VERSION 5.8 ;
BUSBITCHARS "[]" ;
DIVIDERCHAR "/" ;
UNITS
    DATABASE MICRONS 1000 ;
END UNITS

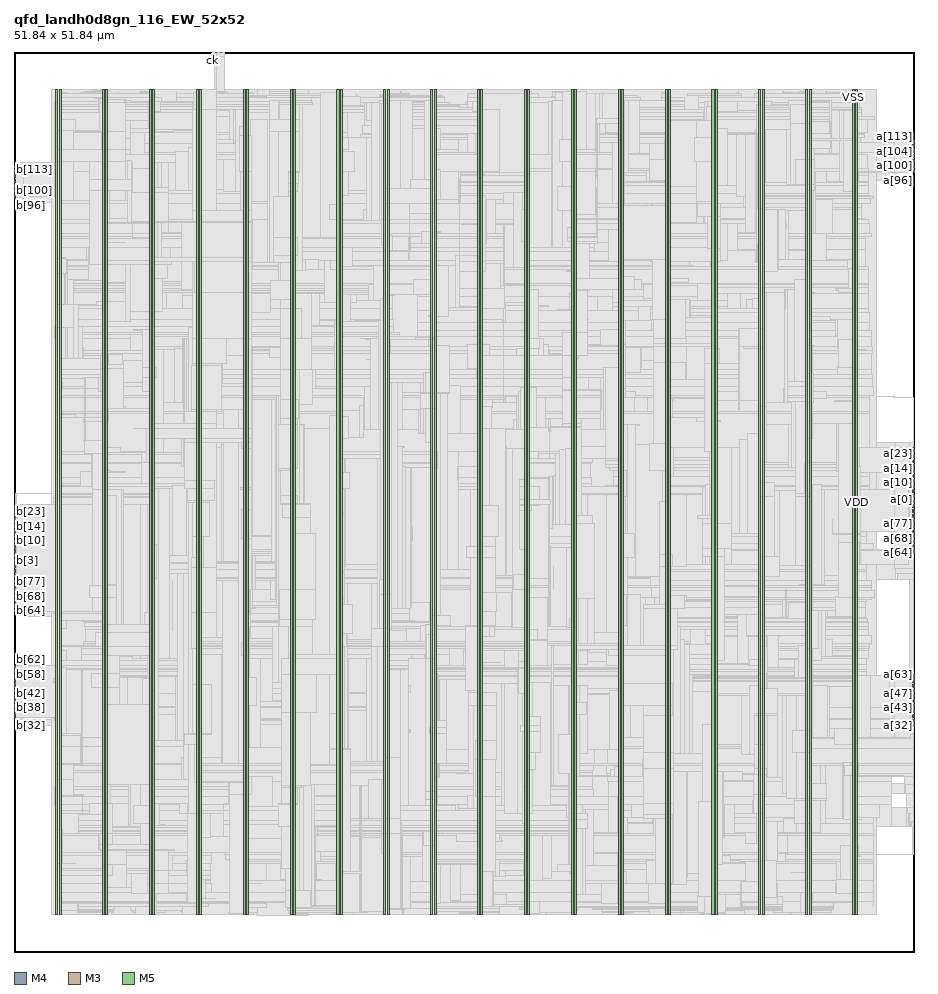
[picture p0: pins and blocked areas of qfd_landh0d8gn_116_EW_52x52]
MACRO qfd_landh0d8gn_116_EW_52x52
  FOREIGN qfd_landh0d8gn_116_EW_52x52 0 0 ;
  CLASS BLOCK ;
  SIZE 51.84 BY 51.84 ;
  PIN a[0]
    DIRECTION INPUT ;
    USE SIGNAL ;
    PORT
      LAYER M4 ;
        RECT  51.756 26.064 51.84 26.088 ;
    END
  END a[0]
  PIN a[100]
    DIRECTION INPUT ;
    USE SIGNAL ;
    PORT
      LAYER M4 ;
        RECT  51.756 45.264 51.84 45.288 ;
    END
  END a[100]
  PIN a[101]
    DIRECTION INPUT ;
    USE SIGNAL ;
    PORT
      LAYER M4 ;
        RECT  51.756 45.36 51.84 45.384 ;
    END
  END a[101]
  PIN a[102]
    DIRECTION INPUT ;
    USE SIGNAL ;
    PORT
      LAYER M4 ;
        RECT  51.756 45.456 51.84 45.48 ;
    END
  END a[102]
  PIN a[103]
    DIRECTION INPUT ;
    USE SIGNAL ;
    PORT
      LAYER M4 ;
        RECT  51.756 45.552 51.84 45.576 ;
    END
  END a[103]
  PIN a[104]
    DIRECTION INPUT ;
    USE SIGNAL ;
    PORT
      LAYER M4 ;
        RECT  51.756 45.648 51.84 45.672 ;
    END
  END a[104]
  PIN a[105]
    DIRECTION INPUT ;
    USE SIGNAL ;
    PORT
      LAYER M4 ;
        RECT  51.756 45.744 51.84 45.768 ;
    END
  END a[105]
  PIN a[106]
    DIRECTION INPUT ;
    USE SIGNAL ;
    PORT
      LAYER M4 ;
        RECT  51.756 45.84 51.84 45.864 ;
    END
  END a[106]
  PIN a[107]
    DIRECTION INPUT ;
    USE SIGNAL ;
    PORT
      LAYER M4 ;
        RECT  51.756 45.936 51.84 45.96 ;
    END
  END a[107]
  PIN a[108]
    DIRECTION INPUT ;
    USE SIGNAL ;
    PORT
      LAYER M4 ;
        RECT  51.756 46.032 51.84 46.056 ;
    END
  END a[108]
  PIN a[109]
    DIRECTION INPUT ;
    USE SIGNAL ;
    PORT
      LAYER M4 ;
        RECT  51.756 46.128 51.84 46.152 ;
    END
  END a[109]
  PIN a[10]
    DIRECTION INPUT ;
    USE SIGNAL ;
    PORT
      LAYER M4 ;
        RECT  51.756 27.024 51.84 27.048 ;
    END
  END a[10]
  PIN a[110]
    DIRECTION INPUT ;
    USE SIGNAL ;
    PORT
      LAYER M4 ;
        RECT  51.756 46.224 51.84 46.248 ;
    END
  END a[110]
  PIN a[111]
    DIRECTION INPUT ;
    USE SIGNAL ;
    PORT
      LAYER M4 ;
        RECT  51.756 46.32 51.84 46.344 ;
    END
  END a[111]
  PIN a[112]
    DIRECTION INPUT ;
    USE SIGNAL ;
    PORT
      LAYER M4 ;
        RECT  51.756 46.416 51.84 46.44 ;
    END
  END a[112]
  PIN a[113]
    DIRECTION INPUT ;
    USE SIGNAL ;
    PORT
      LAYER M4 ;
        RECT  51.756 46.512 51.84 46.536 ;
    END
  END a[113]
  PIN a[114]
    DIRECTION INPUT ;
    USE SIGNAL ;
    PORT
      LAYER M4 ;
        RECT  51.756 46.608 51.84 46.632 ;
    END
  END a[114]
  PIN a[115]
    DIRECTION INPUT ;
    USE SIGNAL ;
    PORT
      LAYER M4 ;
        RECT  51.756 46.704 51.84 46.728 ;
    END
  END a[115]
  PIN a[11]
    DIRECTION INPUT ;
    USE SIGNAL ;
    PORT
      LAYER M4 ;
        RECT  51.756 27.12 51.84 27.144 ;
    END
  END a[11]
  PIN a[12]
    DIRECTION INPUT ;
    USE SIGNAL ;
    PORT
      LAYER M4 ;
        RECT  51.756 27.216 51.84 27.24 ;
    END
  END a[12]
  PIN a[13]
    DIRECTION INPUT ;
    USE SIGNAL ;
    PORT
      LAYER M4 ;
        RECT  51.756 27.312 51.84 27.336 ;
    END
  END a[13]
  PIN a[14]
    DIRECTION INPUT ;
    USE SIGNAL ;
    PORT
      LAYER M4 ;
        RECT  51.756 27.408 51.84 27.432 ;
    END
  END a[14]
  PIN a[15]
    DIRECTION INPUT ;
    USE SIGNAL ;
    PORT
      LAYER M4 ;
        RECT  51.756 27.504 51.84 27.528 ;
    END
  END a[15]
  PIN a[16]
    DIRECTION INPUT ;
    USE SIGNAL ;
    PORT
      LAYER M4 ;
        RECT  51.756 27.6 51.84 27.624 ;
    END
  END a[16]
  PIN a[17]
    DIRECTION INPUT ;
    USE SIGNAL ;
    PORT
      LAYER M4 ;
        RECT  51.756 27.696 51.84 27.72 ;
    END
  END a[17]
  PIN a[18]
    DIRECTION INPUT ;
    USE SIGNAL ;
    PORT
      LAYER M4 ;
        RECT  51.756 27.792 51.84 27.816 ;
    END
  END a[18]
  PIN a[19]
    DIRECTION INPUT ;
    USE SIGNAL ;
    PORT
      LAYER M4 ;
        RECT  51.756 27.888 51.84 27.912 ;
    END
  END a[19]
  PIN a[1]
    DIRECTION INPUT ;
    USE SIGNAL ;
    PORT
      LAYER M4 ;
        RECT  51.756 26.16 51.84 26.184 ;
    END
  END a[1]
  PIN a[20]
    DIRECTION INPUT ;
    USE SIGNAL ;
    PORT
      LAYER M4 ;
        RECT  51.756 27.984 51.84 28.008 ;
    END
  END a[20]
  PIN a[21]
    DIRECTION INPUT ;
    USE SIGNAL ;
    PORT
      LAYER M4 ;
        RECT  51.756 28.08 51.84 28.104 ;
    END
  END a[21]
  PIN a[22]
    DIRECTION INPUT ;
    USE SIGNAL ;
    PORT
      LAYER M4 ;
        RECT  51.756 28.176 51.84 28.2 ;
    END
  END a[22]
  PIN a[23]
    DIRECTION INPUT ;
    USE SIGNAL ;
    PORT
      LAYER M4 ;
        RECT  51.756 28.272 51.84 28.296 ;
    END
  END a[23]
  PIN a[24]
    DIRECTION INPUT ;
    USE SIGNAL ;
    PORT
      LAYER M4 ;
        RECT  51.756 28.368 51.84 28.392 ;
    END
  END a[24]
  PIN a[25]
    DIRECTION INPUT ;
    USE SIGNAL ;
    PORT
      LAYER M4 ;
        RECT  51.756 28.464 51.84 28.488 ;
    END
  END a[25]
  PIN a[26]
    DIRECTION INPUT ;
    USE SIGNAL ;
    PORT
      LAYER M4 ;
        RECT  51.756 28.56 51.84 28.584 ;
    END
  END a[26]
  PIN a[27]
    DIRECTION INPUT ;
    USE SIGNAL ;
    PORT
      LAYER M4 ;
        RECT  51.756 28.656 51.84 28.68 ;
    END
  END a[27]
  PIN a[28]
    DIRECTION INPUT ;
    USE SIGNAL ;
    PORT
      LAYER M4 ;
        RECT  51.756 28.752 51.84 28.776 ;
    END
  END a[28]
  PIN a[29]
    DIRECTION INPUT ;
    USE SIGNAL ;
    PORT
      LAYER M4 ;
        RECT  51.756 28.848 51.84 28.872 ;
    END
  END a[29]
  PIN a[2]
    DIRECTION INPUT ;
    USE SIGNAL ;
    PORT
      LAYER M4 ;
        RECT  51.756 26.256 51.84 26.28 ;
    END
  END a[2]
  PIN a[30]
    DIRECTION INPUT ;
    USE SIGNAL ;
    PORT
      LAYER M4 ;
        RECT  51.756 28.944 51.84 28.968 ;
    END
  END a[30]
  PIN a[31]
    DIRECTION INPUT ;
    USE SIGNAL ;
    PORT
      LAYER M4 ;
        RECT  51.756 29.04 51.84 29.064 ;
    END
  END a[31]
  PIN a[32]
    DIRECTION INPUT ;
    USE SIGNAL ;
    PORT
      LAYER M4 ;
        RECT  51.756 13.008 51.84 13.032 ;
    END
  END a[32]
  PIN a[33]
    DIRECTION INPUT ;
    USE SIGNAL ;
    PORT
      LAYER M4 ;
        RECT  51.756 13.104 51.84 13.128 ;
    END
  END a[33]
  PIN a[34]
    DIRECTION INPUT ;
    USE SIGNAL ;
    PORT
      LAYER M4 ;
        RECT  51.756 13.2 51.84 13.224 ;
    END
  END a[34]
  PIN a[35]
    DIRECTION INPUT ;
    USE SIGNAL ;
    PORT
      LAYER M4 ;
        RECT  51.756 13.296 51.84 13.32 ;
    END
  END a[35]
  PIN a[36]
    DIRECTION INPUT ;
    USE SIGNAL ;
    PORT
      LAYER M4 ;
        RECT  51.756 13.392 51.84 13.416 ;
    END
  END a[36]
  PIN a[37]
    DIRECTION INPUT ;
    USE SIGNAL ;
    PORT
      LAYER M4 ;
        RECT  51.756 13.488 51.84 13.512 ;
    END
  END a[37]
  PIN a[38]
    DIRECTION INPUT ;
    USE SIGNAL ;
    PORT
      LAYER M4 ;
        RECT  51.756 13.584 51.84 13.608 ;
    END
  END a[38]
  PIN a[39]
    DIRECTION INPUT ;
    USE SIGNAL ;
    PORT
      LAYER M4 ;
        RECT  51.756 13.68 51.84 13.704 ;
    END
  END a[39]
  PIN a[3]
    DIRECTION INPUT ;
    USE SIGNAL ;
    PORT
      LAYER M4 ;
        RECT  51.756 26.352 51.84 26.376 ;
    END
  END a[3]
  PIN a[40]
    DIRECTION INPUT ;
    USE SIGNAL ;
    PORT
      LAYER M4 ;
        RECT  51.756 13.776 51.84 13.8 ;
    END
  END a[40]
  PIN a[41]
    DIRECTION INPUT ;
    USE SIGNAL ;
    PORT
      LAYER M4 ;
        RECT  51.756 13.872 51.84 13.896 ;
    END
  END a[41]
  PIN a[42]
    DIRECTION INPUT ;
    USE SIGNAL ;
    PORT
      LAYER M4 ;
        RECT  51.756 13.968 51.84 13.992 ;
    END
  END a[42]
  PIN a[43]
    DIRECTION INPUT ;
    USE SIGNAL ;
    PORT
      LAYER M4 ;
        RECT  51.756 14.064 51.84 14.088 ;
    END
  END a[43]
  PIN a[44]
    DIRECTION INPUT ;
    USE SIGNAL ;
    PORT
      LAYER M4 ;
        RECT  51.756 14.16 51.84 14.184 ;
    END
  END a[44]
  PIN a[45]
    DIRECTION INPUT ;
    USE SIGNAL ;
    PORT
      LAYER M4 ;
        RECT  51.756 14.256 51.84 14.28 ;
    END
  END a[45]
  PIN a[46]
    DIRECTION INPUT ;
    USE SIGNAL ;
    PORT
      LAYER M4 ;
        RECT  51.756 14.352 51.84 14.376 ;
    END
  END a[46]
  PIN a[47]
    DIRECTION INPUT ;
    USE SIGNAL ;
    PORT
      LAYER M4 ;
        RECT  51.756 14.448 51.84 14.472 ;
    END
  END a[47]
  PIN a[48]
    DIRECTION INPUT ;
    USE SIGNAL ;
    PORT
      LAYER M4 ;
        RECT  51.756 14.544 51.84 14.568 ;
    END
  END a[48]
  PIN a[49]
    DIRECTION INPUT ;
    USE SIGNAL ;
    PORT
      LAYER M4 ;
        RECT  51.756 14.64 51.84 14.664 ;
    END
  END a[49]
  PIN a[4]
    DIRECTION INPUT ;
    USE SIGNAL ;
    PORT
      LAYER M4 ;
        RECT  51.756 26.448 51.84 26.472 ;
    END
  END a[4]
  PIN a[50]
    DIRECTION INPUT ;
    USE SIGNAL ;
    PORT
      LAYER M4 ;
        RECT  51.756 14.736 51.84 14.76 ;
    END
  END a[50]
  PIN a[51]
    DIRECTION INPUT ;
    USE SIGNAL ;
    PORT
      LAYER M4 ;
        RECT  51.756 14.832 51.84 14.856 ;
    END
  END a[51]
  PIN a[52]
    DIRECTION INPUT ;
    USE SIGNAL ;
    PORT
      LAYER M4 ;
        RECT  51.756 14.928 51.84 14.952 ;
    END
  END a[52]
  PIN a[53]
    DIRECTION INPUT ;
    USE SIGNAL ;
    PORT
      LAYER M4 ;
        RECT  51.756 15.024 51.84 15.048 ;
    END
  END a[53]
  PIN a[54]
    DIRECTION INPUT ;
    USE SIGNAL ;
    PORT
      LAYER M4 ;
        RECT  51.756 15.12 51.84 15.144 ;
    END
  END a[54]
  PIN a[55]
    DIRECTION INPUT ;
    USE SIGNAL ;
    PORT
      LAYER M4 ;
        RECT  51.756 15.216 51.84 15.24 ;
    END
  END a[55]
  PIN a[56]
    DIRECTION INPUT ;
    USE SIGNAL ;
    PORT
      LAYER M4 ;
        RECT  51.756 15.312 51.84 15.336 ;
    END
  END a[56]
  PIN a[57]
    DIRECTION INPUT ;
    USE SIGNAL ;
    PORT
      LAYER M4 ;
        RECT  51.756 15.408 51.84 15.432 ;
    END
  END a[57]
  PIN a[58]
    DIRECTION INPUT ;
    USE SIGNAL ;
    PORT
      LAYER M4 ;
        RECT  51.756 15.504 51.84 15.528 ;
    END
  END a[58]
  PIN a[59]
    DIRECTION INPUT ;
    USE SIGNAL ;
    PORT
      LAYER M4 ;
        RECT  51.756 15.6 51.84 15.624 ;
    END
  END a[59]
  PIN a[5]
    DIRECTION INPUT ;
    USE SIGNAL ;
    PORT
      LAYER M4 ;
        RECT  51.756 26.544 51.84 26.568 ;
    END
  END a[5]
  PIN a[60]
    DIRECTION INPUT ;
    USE SIGNAL ;
    PORT
      LAYER M4 ;
        RECT  51.756 15.696 51.84 15.72 ;
    END
  END a[60]
  PIN a[61]
    DIRECTION INPUT ;
    USE SIGNAL ;
    PORT
      LAYER M4 ;
        RECT  51.756 15.792 51.84 15.816 ;
    END
  END a[61]
  PIN a[62]
    DIRECTION INPUT ;
    USE SIGNAL ;
    PORT
      LAYER M4 ;
        RECT  51.756 15.888 51.84 15.912 ;
    END
  END a[62]
  PIN a[63]
    DIRECTION INPUT ;
    USE SIGNAL ;
    PORT
      LAYER M4 ;
        RECT  51.756 15.984 51.84 16.008 ;
    END
  END a[63]
  PIN a[64]
    DIRECTION INPUT ;
    USE SIGNAL ;
    PORT
      LAYER M4 ;
        RECT  51.756 22.992 51.84 23.016 ;
    END
  END a[64]
  PIN a[65]
    DIRECTION INPUT ;
    USE SIGNAL ;
    PORT
      LAYER M4 ;
        RECT  51.756 23.088 51.84 23.112 ;
    END
  END a[65]
  PIN a[66]
    DIRECTION INPUT ;
    USE SIGNAL ;
    PORT
      LAYER M4 ;
        RECT  51.756 23.184 51.84 23.208 ;
    END
  END a[66]
  PIN a[67]
    DIRECTION INPUT ;
    USE SIGNAL ;
    PORT
      LAYER M4 ;
        RECT  51.756 23.28 51.84 23.304 ;
    END
  END a[67]
  PIN a[68]
    DIRECTION INPUT ;
    USE SIGNAL ;
    PORT
      LAYER M4 ;
        RECT  51.756 23.376 51.84 23.4 ;
    END
  END a[68]
  PIN a[69]
    DIRECTION INPUT ;
    USE SIGNAL ;
    PORT
      LAYER M4 ;
        RECT  51.756 23.472 51.84 23.496 ;
    END
  END a[69]
  PIN a[6]
    DIRECTION INPUT ;
    USE SIGNAL ;
    PORT
      LAYER M4 ;
        RECT  51.756 26.64 51.84 26.664 ;
    END
  END a[6]
  PIN a[70]
    DIRECTION INPUT ;
    USE SIGNAL ;
    PORT
      LAYER M4 ;
        RECT  51.756 23.568 51.84 23.592 ;
    END
  END a[70]
  PIN a[71]
    DIRECTION INPUT ;
    USE SIGNAL ;
    PORT
      LAYER M4 ;
        RECT  51.756 23.664 51.84 23.688 ;
    END
  END a[71]
  PIN a[72]
    DIRECTION INPUT ;
    USE SIGNAL ;
    PORT
      LAYER M4 ;
        RECT  51.756 23.76 51.84 23.784 ;
    END
  END a[72]
  PIN a[73]
    DIRECTION INPUT ;
    USE SIGNAL ;
    PORT
      LAYER M4 ;
        RECT  51.756 23.856 51.84 23.88 ;
    END
  END a[73]
  PIN a[74]
    DIRECTION INPUT ;
    USE SIGNAL ;
    PORT
      LAYER M4 ;
        RECT  51.756 23.952 51.84 23.976 ;
    END
  END a[74]
  PIN a[75]
    DIRECTION INPUT ;
    USE SIGNAL ;
    PORT
      LAYER M4 ;
        RECT  51.756 24.048 51.84 24.072 ;
    END
  END a[75]
  PIN a[76]
    DIRECTION INPUT ;
    USE SIGNAL ;
    PORT
      LAYER M4 ;
        RECT  51.756 24.144 51.84 24.168 ;
    END
  END a[76]
  PIN a[77]
    DIRECTION INPUT ;
    USE SIGNAL ;
    PORT
      LAYER M4 ;
        RECT  51.756 24.24 51.84 24.264 ;
    END
  END a[77]
  PIN a[78]
    DIRECTION INPUT ;
    USE SIGNAL ;
    PORT
      LAYER M4 ;
        RECT  51.756 24.336 51.84 24.36 ;
    END
  END a[78]
  PIN a[79]
    DIRECTION INPUT ;
    USE SIGNAL ;
    PORT
      LAYER M4 ;
        RECT  51.756 24.432 51.84 24.456 ;
    END
  END a[79]
  PIN a[7]
    DIRECTION INPUT ;
    USE SIGNAL ;
    PORT
      LAYER M4 ;
        RECT  51.756 26.736 51.84 26.76 ;
    END
  END a[7]
  PIN a[80]
    DIRECTION INPUT ;
    USE SIGNAL ;
    PORT
      LAYER M4 ;
        RECT  51.756 24.528 51.84 24.552 ;
    END
  END a[80]
  PIN a[81]
    DIRECTION INPUT ;
    USE SIGNAL ;
    PORT
      LAYER M4 ;
        RECT  51.756 24.624 51.84 24.648 ;
    END
  END a[81]
  PIN a[82]
    DIRECTION INPUT ;
    USE SIGNAL ;
    PORT
      LAYER M4 ;
        RECT  51.756 24.72 51.84 24.744 ;
    END
  END a[82]
  PIN a[83]
    DIRECTION INPUT ;
    USE SIGNAL ;
    PORT
      LAYER M4 ;
        RECT  51.756 24.816 51.84 24.84 ;
    END
  END a[83]
  PIN a[84]
    DIRECTION INPUT ;
    USE SIGNAL ;
    PORT
      LAYER M4 ;
        RECT  51.756 24.912 51.84 24.936 ;
    END
  END a[84]
  PIN a[85]
    DIRECTION INPUT ;
    USE SIGNAL ;
    PORT
      LAYER M4 ;
        RECT  51.756 25.008 51.84 25.032 ;
    END
  END a[85]
  PIN a[86]
    DIRECTION INPUT ;
    USE SIGNAL ;
    PORT
      LAYER M4 ;
        RECT  51.756 25.104 51.84 25.128 ;
    END
  END a[86]
  PIN a[87]
    DIRECTION INPUT ;
    USE SIGNAL ;
    PORT
      LAYER M4 ;
        RECT  51.756 25.2 51.84 25.224 ;
    END
  END a[87]
  PIN a[88]
    DIRECTION INPUT ;
    USE SIGNAL ;
    PORT
      LAYER M4 ;
        RECT  51.756 25.296 51.84 25.32 ;
    END
  END a[88]
  PIN a[89]
    DIRECTION INPUT ;
    USE SIGNAL ;
    PORT
      LAYER M4 ;
        RECT  51.756 25.392 51.84 25.416 ;
    END
  END a[89]
  PIN a[8]
    DIRECTION INPUT ;
    USE SIGNAL ;
    PORT
      LAYER M4 ;
        RECT  51.756 26.832 51.84 26.856 ;
    END
  END a[8]
  PIN a[90]
    DIRECTION INPUT ;
    USE SIGNAL ;
    PORT
      LAYER M4 ;
        RECT  51.756 25.488 51.84 25.512 ;
    END
  END a[90]
  PIN a[91]
    DIRECTION INPUT ;
    USE SIGNAL ;
    PORT
      LAYER M4 ;
        RECT  51.756 25.584 51.84 25.608 ;
    END
  END a[91]
  PIN a[92]
    DIRECTION INPUT ;
    USE SIGNAL ;
    PORT
      LAYER M4 ;
        RECT  51.756 25.68 51.84 25.704 ;
    END
  END a[92]
  PIN a[93]
    DIRECTION INPUT ;
    USE SIGNAL ;
    PORT
      LAYER M4 ;
        RECT  51.756 25.776 51.84 25.8 ;
    END
  END a[93]
  PIN a[94]
    DIRECTION INPUT ;
    USE SIGNAL ;
    PORT
      LAYER M4 ;
        RECT  51.756 25.872 51.84 25.896 ;
    END
  END a[94]
  PIN a[95]
    DIRECTION INPUT ;
    USE SIGNAL ;
    PORT
      LAYER M4 ;
        RECT  51.756 25.968 51.84 25.992 ;
    END
  END a[95]
  PIN a[96]
    DIRECTION INPUT ;
    USE SIGNAL ;
    PORT
      LAYER M4 ;
        RECT  51.756 44.88 51.84 44.904 ;
    END
  END a[96]
  PIN a[97]
    DIRECTION INPUT ;
    USE SIGNAL ;
    PORT
      LAYER M4 ;
        RECT  51.756 44.976 51.84 45 ;
    END
  END a[97]
  PIN a[98]
    DIRECTION INPUT ;
    USE SIGNAL ;
    PORT
      LAYER M4 ;
        RECT  51.756 45.072 51.84 45.096 ;
    END
  END a[98]
  PIN a[99]
    DIRECTION INPUT ;
    USE SIGNAL ;
    PORT
      LAYER M4 ;
        RECT  51.756 45.168 51.84 45.192 ;
    END
  END a[99]
  PIN a[9]
    DIRECTION INPUT ;
    USE SIGNAL ;
    PORT
      LAYER M4 ;
        RECT  51.756 26.928 51.84 26.952 ;
    END
  END a[9]
  PIN b[0]
    DIRECTION OUTPUT ;
    USE SIGNAL ;
    PORT
      LAYER M4 ;
        RECT  0 22.704 0.084 22.728 ;
    END
  END b[0]
  PIN b[100]
    DIRECTION OUTPUT ;
    USE SIGNAL ;
    PORT
      LAYER M4 ;
        RECT  0 43.824 0.084 43.848 ;
    END
  END b[100]
  PIN b[101]
    DIRECTION OUTPUT ;
    USE SIGNAL ;
    PORT
      LAYER M4 ;
        RECT  0 43.92 0.084 43.944 ;
    END
  END b[101]
  PIN b[102]
    DIRECTION OUTPUT ;
    USE SIGNAL ;
    PORT
      LAYER M4 ;
        RECT  0 44.016 0.084 44.04 ;
    END
  END b[102]
  PIN b[103]
    DIRECTION OUTPUT ;
    USE SIGNAL ;
    PORT
      LAYER M4 ;
        RECT  0 44.112 0.084 44.136 ;
    END
  END b[103]
  PIN b[104]
    DIRECTION OUTPUT ;
    USE SIGNAL ;
    PORT
      LAYER M4 ;
        RECT  0 44.208 0.084 44.232 ;
    END
  END b[104]
  PIN b[105]
    DIRECTION OUTPUT ;
    USE SIGNAL ;
    PORT
      LAYER M4 ;
        RECT  0 44.304 0.084 44.328 ;
    END
  END b[105]
  PIN b[106]
    DIRECTION OUTPUT ;
    USE SIGNAL ;
    PORT
      LAYER M4 ;
        RECT  0 44.4 0.084 44.424 ;
    END
  END b[106]
  PIN b[107]
    DIRECTION OUTPUT ;
    USE SIGNAL ;
    PORT
      LAYER M4 ;
        RECT  0 44.496 0.084 44.52 ;
    END
  END b[107]
  PIN b[108]
    DIRECTION OUTPUT ;
    USE SIGNAL ;
    PORT
      LAYER M4 ;
        RECT  0 44.592 0.084 44.616 ;
    END
  END b[108]
  PIN b[109]
    DIRECTION OUTPUT ;
    USE SIGNAL ;
    PORT
      LAYER M4 ;
        RECT  0 44.688 0.084 44.712 ;
    END
  END b[109]
  PIN b[10]
    DIRECTION OUTPUT ;
    USE SIGNAL ;
    PORT
      LAYER M4 ;
        RECT  0 23.664 0.084 23.688 ;
    END
  END b[10]
  PIN b[110]
    DIRECTION OUTPUT ;
    USE SIGNAL ;
    PORT
      LAYER M4 ;
        RECT  0 44.784 0.084 44.808 ;
    END
  END b[110]
  PIN b[111]
    DIRECTION OUTPUT ;
    USE SIGNAL ;
    PORT
      LAYER M4 ;
        RECT  0 44.88 0.084 44.904 ;
    END
  END b[111]
  PIN b[112]
    DIRECTION OUTPUT ;
    USE SIGNAL ;
    PORT
      LAYER M4 ;
        RECT  0 44.976 0.084 45 ;
    END
  END b[112]
  PIN b[113]
    DIRECTION OUTPUT ;
    USE SIGNAL ;
    PORT
      LAYER M4 ;
        RECT  0 45.072 0.084 45.096 ;
    END
  END b[113]
  PIN b[114]
    DIRECTION OUTPUT ;
    USE SIGNAL ;
    PORT
      LAYER M4 ;
        RECT  0 45.168 0.084 45.192 ;
    END
  END b[114]
  PIN b[115]
    DIRECTION OUTPUT ;
    USE SIGNAL ;
    PORT
      LAYER M4 ;
        RECT  0 45.264 0.084 45.288 ;
    END
  END b[115]
  PIN b[11]
    DIRECTION OUTPUT ;
    USE SIGNAL ;
    PORT
      LAYER M4 ;
        RECT  0 23.76 0.084 23.784 ;
    END
  END b[11]
  PIN b[12]
    DIRECTION OUTPUT ;
    USE SIGNAL ;
    PORT
      LAYER M4 ;
        RECT  0 23.856 0.084 23.88 ;
    END
  END b[12]
  PIN b[13]
    DIRECTION OUTPUT ;
    USE SIGNAL ;
    PORT
      LAYER M4 ;
        RECT  0 23.952 0.084 23.976 ;
    END
  END b[13]
  PIN b[14]
    DIRECTION OUTPUT ;
    USE SIGNAL ;
    PORT
      LAYER M4 ;
        RECT  0 24.048 0.084 24.072 ;
    END
  END b[14]
  PIN b[15]
    DIRECTION OUTPUT ;
    USE SIGNAL ;
    PORT
      LAYER M4 ;
        RECT  0 24.144 0.084 24.168 ;
    END
  END b[15]
  PIN b[16]
    DIRECTION OUTPUT ;
    USE SIGNAL ;
    PORT
      LAYER M4 ;
        RECT  0 24.24 0.084 24.264 ;
    END
  END b[16]
  PIN b[17]
    DIRECTION OUTPUT ;
    USE SIGNAL ;
    PORT
      LAYER M4 ;
        RECT  0 24.336 0.084 24.36 ;
    END
  END b[17]
  PIN b[18]
    DIRECTION OUTPUT ;
    USE SIGNAL ;
    PORT
      LAYER M4 ;
        RECT  0 24.432 0.084 24.456 ;
    END
  END b[18]
  PIN b[19]
    DIRECTION OUTPUT ;
    USE SIGNAL ;
    PORT
      LAYER M4 ;
        RECT  0 24.528 0.084 24.552 ;
    END
  END b[19]
  PIN b[1]
    DIRECTION OUTPUT ;
    USE SIGNAL ;
    PORT
      LAYER M4 ;
        RECT  0 22.8 0.084 22.824 ;
    END
  END b[1]
  PIN b[20]
    DIRECTION OUTPUT ;
    USE SIGNAL ;
    PORT
      LAYER M4 ;
        RECT  0 24.624 0.084 24.648 ;
    END
  END b[20]
  PIN b[21]
    DIRECTION OUTPUT ;
    USE SIGNAL ;
    PORT
      LAYER M4 ;
        RECT  0 24.72 0.084 24.744 ;
    END
  END b[21]
  PIN b[22]
    DIRECTION OUTPUT ;
    USE SIGNAL ;
    PORT
      LAYER M4 ;
        RECT  0 24.816 0.084 24.84 ;
    END
  END b[22]
  PIN b[23]
    DIRECTION OUTPUT ;
    USE SIGNAL ;
    PORT
      LAYER M4 ;
        RECT  0 24.912 0.084 24.936 ;
    END
  END b[23]
  PIN b[24]
    DIRECTION OUTPUT ;
    USE SIGNAL ;
    PORT
      LAYER M4 ;
        RECT  0 25.008 0.084 25.032 ;
    END
  END b[24]
  PIN b[25]
    DIRECTION OUTPUT ;
    USE SIGNAL ;
    PORT
      LAYER M4 ;
        RECT  0 25.104 0.084 25.128 ;
    END
  END b[25]
  PIN b[26]
    DIRECTION OUTPUT ;
    USE SIGNAL ;
    PORT
      LAYER M4 ;
        RECT  0 25.2 0.084 25.224 ;
    END
  END b[26]
  PIN b[27]
    DIRECTION OUTPUT ;
    USE SIGNAL ;
    PORT
      LAYER M4 ;
        RECT  0 25.296 0.084 25.32 ;
    END
  END b[27]
  PIN b[28]
    DIRECTION OUTPUT ;
    USE SIGNAL ;
    PORT
      LAYER M4 ;
        RECT  0 25.392 0.084 25.416 ;
    END
  END b[28]
  PIN b[29]
    DIRECTION OUTPUT ;
    USE SIGNAL ;
    PORT
      LAYER M4 ;
        RECT  0 25.488 0.084 25.512 ;
    END
  END b[29]
  PIN b[2]
    DIRECTION OUTPUT ;
    USE SIGNAL ;
    PORT
      LAYER M4 ;
        RECT  0 22.896 0.084 22.92 ;
    END
  END b[2]
  PIN b[30]
    DIRECTION OUTPUT ;
    USE SIGNAL ;
    PORT
      LAYER M4 ;
        RECT  0 25.584 0.084 25.608 ;
    END
  END b[30]
  PIN b[31]
    DIRECTION OUTPUT ;
    USE SIGNAL ;
    PORT
      LAYER M4 ;
        RECT  0 25.68 0.084 25.704 ;
    END
  END b[31]
  PIN b[32]
    DIRECTION OUTPUT ;
    USE SIGNAL ;
    PORT
      LAYER M4 ;
        RECT  0 13.488 0.084 13.512 ;
    END
  END b[32]
  PIN b[33]
    DIRECTION OUTPUT ;
    USE SIGNAL ;
    PORT
      LAYER M4 ;
        RECT  0 13.584 0.084 13.608 ;
    END
  END b[33]
  PIN b[34]
    DIRECTION OUTPUT ;
    USE SIGNAL ;
    PORT
      LAYER M4 ;
        RECT  0 13.68 0.084 13.704 ;
    END
  END b[34]
  PIN b[35]
    DIRECTION OUTPUT ;
    USE SIGNAL ;
    PORT
      LAYER M4 ;
        RECT  0 13.776 0.084 13.8 ;
    END
  END b[35]
  PIN b[36]
    DIRECTION OUTPUT ;
    USE SIGNAL ;
    PORT
      LAYER M4 ;
        RECT  0 13.872 0.084 13.896 ;
    END
  END b[36]
  PIN b[37]
    DIRECTION OUTPUT ;
    USE SIGNAL ;
    PORT
      LAYER M4 ;
        RECT  0 13.968 0.084 13.992 ;
    END
  END b[37]
  PIN b[38]
    DIRECTION OUTPUT ;
    USE SIGNAL ;
    PORT
      LAYER M4 ;
        RECT  0 14.064 0.084 14.088 ;
    END
  END b[38]
  PIN b[39]
    DIRECTION OUTPUT ;
    USE SIGNAL ;
    PORT
      LAYER M4 ;
        RECT  0 14.16 0.084 14.184 ;
    END
  END b[39]
  PIN b[3]
    DIRECTION OUTPUT ;
    USE SIGNAL ;
    PORT
      LAYER M4 ;
        RECT  0 22.992 0.084 23.016 ;
    END
  END b[3]
  PIN b[40]
    DIRECTION OUTPUT ;
    USE SIGNAL ;
    PORT
      LAYER M4 ;
        RECT  0 14.256 0.084 14.28 ;
    END
  END b[40]
  PIN b[41]
    DIRECTION OUTPUT ;
    USE SIGNAL ;
    PORT
      LAYER M4 ;
        RECT  0 14.352 0.084 14.376 ;
    END
  END b[41]
  PIN b[42]
    DIRECTION OUTPUT ;
    USE SIGNAL ;
    PORT
      LAYER M4 ;
        RECT  0 14.448 0.084 14.472 ;
    END
  END b[42]
  PIN b[43]
    DIRECTION OUTPUT ;
    USE SIGNAL ;
    PORT
      LAYER M4 ;
        RECT  0 14.544 0.084 14.568 ;
    END
  END b[43]
  PIN b[44]
    DIRECTION OUTPUT ;
    USE SIGNAL ;
    PORT
      LAYER M4 ;
        RECT  0 14.64 0.084 14.664 ;
    END
  END b[44]
  PIN b[45]
    DIRECTION OUTPUT ;
    USE SIGNAL ;
    PORT
      LAYER M4 ;
        RECT  0 14.736 0.084 14.76 ;
    END
  END b[45]
  PIN b[46]
    DIRECTION OUTPUT ;
    USE SIGNAL ;
    PORT
      LAYER M4 ;
        RECT  0 14.832 0.084 14.856 ;
    END
  END b[46]
  PIN b[47]
    DIRECTION OUTPUT ;
    USE SIGNAL ;
    PORT
      LAYER M4 ;
        RECT  0 14.928 0.084 14.952 ;
    END
  END b[47]
  PIN b[48]
    DIRECTION OUTPUT ;
    USE SIGNAL ;
    PORT
      LAYER M4 ;
        RECT  0 15.024 0.084 15.048 ;
    END
  END b[48]
  PIN b[49]
    DIRECTION OUTPUT ;
    USE SIGNAL ;
    PORT
      LAYER M4 ;
        RECT  0 15.12 0.084 15.144 ;
    END
  END b[49]
  PIN b[4]
    DIRECTION OUTPUT ;
    USE SIGNAL ;
    PORT
      LAYER M4 ;
        RECT  0 23.088 0.084 23.112 ;
    END
  END b[4]
  PIN b[50]
    DIRECTION OUTPUT ;
    USE SIGNAL ;
    PORT
      LAYER M4 ;
        RECT  0 15.216 0.084 15.24 ;
    END
  END b[50]
  PIN b[51]
    DIRECTION OUTPUT ;
    USE SIGNAL ;
    PORT
      LAYER M4 ;
        RECT  0 15.312 0.084 15.336 ;
    END
  END b[51]
  PIN b[52]
    DIRECTION OUTPUT ;
    USE SIGNAL ;
    PORT
      LAYER M4 ;
        RECT  0 15.408 0.084 15.432 ;
    END
  END b[52]
  PIN b[53]
    DIRECTION OUTPUT ;
    USE SIGNAL ;
    PORT
      LAYER M4 ;
        RECT  0 15.504 0.084 15.528 ;
    END
  END b[53]
  PIN b[54]
    DIRECTION OUTPUT ;
    USE SIGNAL ;
    PORT
      LAYER M4 ;
        RECT  0 15.6 0.084 15.624 ;
    END
  END b[54]
  PIN b[55]
    DIRECTION OUTPUT ;
    USE SIGNAL ;
    PORT
      LAYER M4 ;
        RECT  0 15.696 0.084 15.72 ;
    END
  END b[55]
  PIN b[56]
    DIRECTION OUTPUT ;
    USE SIGNAL ;
    PORT
      LAYER M4 ;
        RECT  0 15.792 0.084 15.816 ;
    END
  END b[56]
  PIN b[57]
    DIRECTION OUTPUT ;
    USE SIGNAL ;
    PORT
      LAYER M4 ;
        RECT  0 15.888 0.084 15.912 ;
    END
  END b[57]
  PIN b[58]
    DIRECTION OUTPUT ;
    USE SIGNAL ;
    PORT
      LAYER M4 ;
        RECT  0 15.984 0.084 16.008 ;
    END
  END b[58]
  PIN b[59]
    DIRECTION OUTPUT ;
    USE SIGNAL ;
    PORT
      LAYER M4 ;
        RECT  0 16.08 0.084 16.104 ;
    END
  END b[59]
  PIN b[5]
    DIRECTION OUTPUT ;
    USE SIGNAL ;
    PORT
      LAYER M4 ;
        RECT  0 23.184 0.084 23.208 ;
    END
  END b[5]
  PIN b[60]
    DIRECTION OUTPUT ;
    USE SIGNAL ;
    PORT
      LAYER M4 ;
        RECT  0 16.176 0.084 16.2 ;
    END
  END b[60]
  PIN b[61]
    DIRECTION OUTPUT ;
    USE SIGNAL ;
    PORT
      LAYER M4 ;
        RECT  0 16.272 0.084 16.296 ;
    END
  END b[61]
  PIN b[62]
    DIRECTION OUTPUT ;
    USE SIGNAL ;
    PORT
      LAYER M4 ;
        RECT  0 16.368 0.084 16.392 ;
    END
  END b[62]
  PIN b[63]
    DIRECTION OUTPUT ;
    USE SIGNAL ;
    PORT
      LAYER M4 ;
        RECT  0 16.464 0.084 16.488 ;
    END
  END b[63]
  PIN b[64]
    DIRECTION OUTPUT ;
    USE SIGNAL ;
    PORT
      LAYER M4 ;
        RECT  0 19.632 0.084 19.656 ;
    END
  END b[64]
  PIN b[65]
    DIRECTION OUTPUT ;
    USE SIGNAL ;
    PORT
      LAYER M4 ;
        RECT  0 19.728 0.084 19.752 ;
    END
  END b[65]
  PIN b[66]
    DIRECTION OUTPUT ;
    USE SIGNAL ;
    PORT
      LAYER M4 ;
        RECT  0 19.824 0.084 19.848 ;
    END
  END b[66]
  PIN b[67]
    DIRECTION OUTPUT ;
    USE SIGNAL ;
    PORT
      LAYER M4 ;
        RECT  0 19.92 0.084 19.944 ;
    END
  END b[67]
  PIN b[68]
    DIRECTION OUTPUT ;
    USE SIGNAL ;
    PORT
      LAYER M4 ;
        RECT  0 20.016 0.084 20.04 ;
    END
  END b[68]
  PIN b[69]
    DIRECTION OUTPUT ;
    USE SIGNAL ;
    PORT
      LAYER M4 ;
        RECT  0 20.112 0.084 20.136 ;
    END
  END b[69]
  PIN b[6]
    DIRECTION OUTPUT ;
    USE SIGNAL ;
    PORT
      LAYER M4 ;
        RECT  0 23.28 0.084 23.304 ;
    END
  END b[6]
  PIN b[70]
    DIRECTION OUTPUT ;
    USE SIGNAL ;
    PORT
      LAYER M4 ;
        RECT  0 20.208 0.084 20.232 ;
    END
  END b[70]
  PIN b[71]
    DIRECTION OUTPUT ;
    USE SIGNAL ;
    PORT
      LAYER M4 ;
        RECT  0 20.304 0.084 20.328 ;
    END
  END b[71]
  PIN b[72]
    DIRECTION OUTPUT ;
    USE SIGNAL ;
    PORT
      LAYER M4 ;
        RECT  0 20.4 0.084 20.424 ;
    END
  END b[72]
  PIN b[73]
    DIRECTION OUTPUT ;
    USE SIGNAL ;
    PORT
      LAYER M4 ;
        RECT  0 20.496 0.084 20.52 ;
    END
  END b[73]
  PIN b[74]
    DIRECTION OUTPUT ;
    USE SIGNAL ;
    PORT
      LAYER M4 ;
        RECT  0 20.592 0.084 20.616 ;
    END
  END b[74]
  PIN b[75]
    DIRECTION OUTPUT ;
    USE SIGNAL ;
    PORT
      LAYER M4 ;
        RECT  0 20.688 0.084 20.712 ;
    END
  END b[75]
  PIN b[76]
    DIRECTION OUTPUT ;
    USE SIGNAL ;
    PORT
      LAYER M4 ;
        RECT  0 20.784 0.084 20.808 ;
    END
  END b[76]
  PIN b[77]
    DIRECTION OUTPUT ;
    USE SIGNAL ;
    PORT
      LAYER M4 ;
        RECT  0 20.88 0.084 20.904 ;
    END
  END b[77]
  PIN b[78]
    DIRECTION OUTPUT ;
    USE SIGNAL ;
    PORT
      LAYER M4 ;
        RECT  0 20.976 0.084 21 ;
    END
  END b[78]
  PIN b[79]
    DIRECTION OUTPUT ;
    USE SIGNAL ;
    PORT
      LAYER M4 ;
        RECT  0 21.072 0.084 21.096 ;
    END
  END b[79]
  PIN b[7]
    DIRECTION OUTPUT ;
    USE SIGNAL ;
    PORT
      LAYER M4 ;
        RECT  0 23.376 0.084 23.4 ;
    END
  END b[7]
  PIN b[80]
    DIRECTION OUTPUT ;
    USE SIGNAL ;
    PORT
      LAYER M4 ;
        RECT  0 21.168 0.084 21.192 ;
    END
  END b[80]
  PIN b[81]
    DIRECTION OUTPUT ;
    USE SIGNAL ;
    PORT
      LAYER M4 ;
        RECT  0 21.264 0.084 21.288 ;
    END
  END b[81]
  PIN b[82]
    DIRECTION OUTPUT ;
    USE SIGNAL ;
    PORT
      LAYER M4 ;
        RECT  0 21.36 0.084 21.384 ;
    END
  END b[82]
  PIN b[83]
    DIRECTION OUTPUT ;
    USE SIGNAL ;
    PORT
      LAYER M4 ;
        RECT  0 21.456 0.084 21.48 ;
    END
  END b[83]
  PIN b[84]
    DIRECTION OUTPUT ;
    USE SIGNAL ;
    PORT
      LAYER M4 ;
        RECT  0 21.552 0.084 21.576 ;
    END
  END b[84]
  PIN b[85]
    DIRECTION OUTPUT ;
    USE SIGNAL ;
    PORT
      LAYER M4 ;
        RECT  0 21.648 0.084 21.672 ;
    END
  END b[85]
  PIN b[86]
    DIRECTION OUTPUT ;
    USE SIGNAL ;
    PORT
      LAYER M4 ;
        RECT  0 21.744 0.084 21.768 ;
    END
  END b[86]
  PIN b[87]
    DIRECTION OUTPUT ;
    USE SIGNAL ;
    PORT
      LAYER M4 ;
        RECT  0 21.84 0.084 21.864 ;
    END
  END b[87]
  PIN b[88]
    DIRECTION OUTPUT ;
    USE SIGNAL ;
    PORT
      LAYER M4 ;
        RECT  0 21.936 0.084 21.96 ;
    END
  END b[88]
  PIN b[89]
    DIRECTION OUTPUT ;
    USE SIGNAL ;
    PORT
      LAYER M4 ;
        RECT  0 22.032 0.084 22.056 ;
    END
  END b[89]
  PIN b[8]
    DIRECTION OUTPUT ;
    USE SIGNAL ;
    PORT
      LAYER M4 ;
        RECT  0 23.472 0.084 23.496 ;
    END
  END b[8]
  PIN b[90]
    DIRECTION OUTPUT ;
    USE SIGNAL ;
    PORT
      LAYER M4 ;
        RECT  0 22.128 0.084 22.152 ;
    END
  END b[90]
  PIN b[91]
    DIRECTION OUTPUT ;
    USE SIGNAL ;
    PORT
      LAYER M4 ;
        RECT  0 22.224 0.084 22.248 ;
    END
  END b[91]
  PIN b[92]
    DIRECTION OUTPUT ;
    USE SIGNAL ;
    PORT
      LAYER M4 ;
        RECT  0 22.32 0.084 22.344 ;
    END
  END b[92]
  PIN b[93]
    DIRECTION OUTPUT ;
    USE SIGNAL ;
    PORT
      LAYER M4 ;
        RECT  0 22.416 0.084 22.44 ;
    END
  END b[93]
  PIN b[94]
    DIRECTION OUTPUT ;
    USE SIGNAL ;
    PORT
      LAYER M4 ;
        RECT  0 22.512 0.084 22.536 ;
    END
  END b[94]
  PIN b[95]
    DIRECTION OUTPUT ;
    USE SIGNAL ;
    PORT
      LAYER M4 ;
        RECT  0 22.608 0.084 22.632 ;
    END
  END b[95]
  PIN b[96]
    DIRECTION OUTPUT ;
    USE SIGNAL ;
    PORT
      LAYER M4 ;
        RECT  0 43.44 0.084 43.464 ;
    END
  END b[96]
  PIN b[97]
    DIRECTION OUTPUT ;
    USE SIGNAL ;
    PORT
      LAYER M4 ;
        RECT  0 43.536 0.084 43.56 ;
    END
  END b[97]
  PIN b[98]
    DIRECTION OUTPUT ;
    USE SIGNAL ;
    PORT
      LAYER M4 ;
        RECT  0 43.632 0.084 43.656 ;
    END
  END b[98]
  PIN b[99]
    DIRECTION OUTPUT ;
    USE SIGNAL ;
    PORT
      LAYER M4 ;
        RECT  0 43.728 0.084 43.752 ;
    END
  END b[99]
  PIN b[9]
    DIRECTION OUTPUT ;
    USE SIGNAL ;
    PORT
      LAYER M4 ;
        RECT  0 23.568 0.084 23.592 ;
    END
  END b[9]
  PIN ck
    DIRECTION INPUT ;
    USE SIGNAL ;
    PORT
      LAYER M3 ;
        RECT  11.412 51.803 11.43 51.84 ;
    END
  END ck
  PIN ck_s
    DIRECTION INPUT ;
    USE SIGNAL ;
    PORT
      LAYER M3 ;
        RECT  11.484 51.803 11.502 51.84 ;
    END
  END ck_s
  PIN en
    DIRECTION INPUT ;
    USE SIGNAL ;
    PORT
      LAYER M3 ;
        RECT  11.556 51.803 11.574 51.84 ;
    END
  END en
  PIN fault
    DIRECTION OUTPUT ;
    USE SIGNAL ;
    PORT
      LAYER M3 ;
        RECT  11.628 51.803 11.646 51.84 ;
    END
  END fault
  PIN k0
    DIRECTION INPUT ;
    USE SIGNAL ;
    PORT
      LAYER M3 ;
        RECT  11.7 51.803 11.718 51.84 ;
    END
  END k0
  PIN k1
    DIRECTION INPUT ;
    USE SIGNAL ;
    PORT
      LAYER M3 ;
        RECT  11.772 51.803 11.79 51.84 ;
    END
  END k1
  PIN k2
    DIRECTION INPUT ;
    USE SIGNAL ;
    PORT
      LAYER M3 ;
        RECT  11.844 51.803 11.862 51.84 ;
    END
  END k2
  PIN k3
    DIRECTION INPUT ;
    USE SIGNAL ;
    PORT
      LAYER M3 ;
        RECT  11.916 51.803 11.934 51.84 ;
    END
  END k3
  PIN rs
    DIRECTION INPUT ;
    USE SIGNAL ;
    PORT
      LAYER M3 ;
        RECT  11.988 51.803 12.006 51.84 ;
    END
  END rs
  PIN tie_hi
    DIRECTION OUTPUT ;
    USE SIGNAL ;
    PORT
      LAYER M3 ;
        RECT  12.06 51.803 12.078 51.84 ;
    END
  END tie_hi
  PIN tie_lo
    DIRECTION OUTPUT ;
    USE SIGNAL ;
    PORT
      LAYER M3 ;
        RECT  12.132 51.803 12.15 51.84 ;
    END
  END tie_lo
  PIN VSS
    DIRECTION INOUT ;
    USE GROUND ;
    PORT
      LAYER M5 ;
        RECT  48.3 2.137 48.42 49.703 ;
        RECT  45.6 2.137 45.72 49.703 ;
        RECT  42.9 2.137 43.02 49.703 ;
        RECT  40.2 2.137 40.32 49.703 ;
        RECT  37.5 2.137 37.62 49.703 ;
        RECT  34.8 2.137 34.92 49.703 ;
        RECT  32.1 2.137 32.22 49.703 ;
        RECT  29.4 2.137 29.52 49.703 ;
        RECT  26.7 2.137 26.82 49.703 ;
        RECT  24 2.137 24.12 49.703 ;
        RECT  21.3 2.137 21.42 49.703 ;
        RECT  18.6 2.137 18.72 49.703 ;
        RECT  15.9 2.137 16.02 49.703 ;
        RECT  13.2 2.137 13.32 49.703 ;
        RECT  10.5 2.137 10.62 49.703 ;
        RECT  7.8 2.137 7.92 49.703 ;
        RECT  5.1 2.137 5.22 49.703 ;
        RECT  2.4 2.137 2.52 49.703 ;
    END
  END VSS
  PIN VDD
    DIRECTION INOUT ;
    USE POWER ;
    PORT
      LAYER M5 ;
        RECT  48.492 2.151 48.612 49.689 ;
        RECT  45.792 2.151 45.912 49.689 ;
        RECT  43.092 2.151 43.212 49.689 ;
        RECT  40.392 2.151 40.512 49.689 ;
        RECT  37.692 2.151 37.812 49.689 ;
        RECT  34.992 2.151 35.112 49.689 ;
        RECT  32.292 2.151 32.412 49.689 ;
        RECT  29.592 2.151 29.712 49.689 ;
        RECT  26.892 2.151 27.012 49.689 ;
        RECT  24.192 2.151 24.312 49.689 ;
        RECT  21.492 2.151 21.612 49.689 ;
        RECT  18.792 2.151 18.912 49.689 ;
        RECT  16.092 2.151 16.212 49.689 ;
        RECT  13.392 2.151 13.512 49.689 ;
        RECT  10.692 2.151 10.812 49.689 ;
        RECT  7.992 2.151 8.112 49.689 ;
        RECT  5.292 2.151 5.412 49.689 ;
        RECT  2.592 2.151 2.712 49.689 ;
    END
  END VDD
  OBS
    LAYER RVTN ;
     RECT  2.16 2.16 49.68 2.295 ;
     RECT  2.16 2.565 49.68 2.835 ;
     RECT  2.16 3.105 49.68 3.375 ;
     RECT  2.16 3.645 49.68 3.915 ;
     RECT  2.16 4.185 49.68 4.455 ;
     RECT  2.16 4.725 49.68 4.995 ;
     RECT  2.16 5.265 49.68 5.535 ;
     RECT  2.16 5.805 49.68 6.075 ;
     RECT  2.16 6.345 49.68 6.615 ;
     RECT  2.16 6.885 49.68 7.155 ;
     RECT  2.16 7.425 49.68 7.695 ;
     RECT  2.16 7.965 49.68 8.235 ;
     RECT  2.16 8.505 49.68 8.775 ;
     RECT  2.16 9.045 49.68 9.315 ;
     RECT  2.16 9.585 49.68 9.855 ;
     RECT  2.16 10.125 49.68 10.395 ;
     RECT  2.16 10.665 49.68 10.935 ;
     RECT  2.16 11.205 49.68 11.475 ;
     RECT  2.16 11.745 49.68 12.015 ;
     RECT  2.16 12.285 49.68 12.555 ;
     RECT  2.16 12.825 49.68 13.095 ;
     RECT  2.16 13.365 49.68 13.635 ;
     RECT  2.16 13.905 49.68 14.175 ;
     RECT  2.16 14.445 49.68 14.715 ;
     RECT  2.16 14.985 49.68 15.255 ;
     RECT  2.16 15.525 49.68 15.795 ;
     RECT  2.16 16.065 49.68 16.335 ;
     RECT  2.16 16.605 49.68 16.875 ;
     RECT  2.16 17.145 49.68 17.415 ;
     RECT  2.16 17.685 49.68 17.955 ;
     RECT  2.16 18.225 49.68 18.495 ;
     RECT  2.16 18.765 49.68 19.035 ;
     RECT  2.16 19.305 49.68 19.575 ;
     RECT  2.16 19.845 49.68 20.115 ;
     RECT  2.16 20.385 49.68 20.655 ;
     RECT  2.16 20.925 49.68 21.195 ;
     RECT  2.16 21.465 49.68 21.735 ;
     RECT  2.16 22.005 49.68 22.275 ;
     RECT  2.16 22.545 49.68 22.815 ;
     RECT  2.16 23.085 49.68 23.355 ;
     RECT  2.16 23.625 49.68 23.895 ;
     RECT  2.16 24.165 49.68 24.435 ;
     RECT  2.16 24.705 49.68 24.975 ;
     RECT  2.16 25.245 49.68 25.515 ;
     RECT  2.16 25.785 49.68 26.055 ;
     RECT  2.16 26.325 49.68 26.595 ;
     RECT  2.16 26.865 49.68 27.135 ;
     RECT  2.16 27.405 49.68 27.675 ;
     RECT  2.16 27.945 49.68 28.215 ;
     RECT  2.16 28.485 49.68 28.755 ;
     RECT  2.16 29.025 49.68 29.295 ;
     RECT  2.16 29.565 49.68 29.835 ;
     RECT  2.16 30.105 49.68 30.375 ;
     RECT  2.16 30.645 49.68 30.915 ;
     RECT  2.16 31.185 49.68 31.455 ;
     RECT  2.16 31.725 49.68 31.995 ;
     RECT  2.16 32.265 49.68 32.535 ;
     RECT  2.16 32.805 49.68 33.075 ;
     RECT  2.16 33.345 49.68 33.615 ;
     RECT  2.16 33.885 49.68 34.155 ;
     RECT  2.16 34.425 49.68 34.695 ;
     RECT  2.16 34.965 49.68 35.235 ;
     RECT  2.16 35.505 49.68 35.775 ;
     RECT  2.16 36.045 49.68 36.315 ;
     RECT  2.16 36.585 49.68 36.855 ;
     RECT  2.16 37.125 49.68 37.395 ;
     RECT  2.16 37.665 49.68 37.935 ;
     RECT  2.16 38.205 49.68 38.475 ;
     RECT  2.16 38.745 49.68 39.015 ;
     RECT  2.16 39.285 49.68 39.555 ;
     RECT  2.16 39.825 49.68 40.095 ;
     RECT  2.16 40.365 49.68 40.635 ;
     RECT  2.16 40.905 49.68 41.175 ;
     RECT  2.16 41.445 49.68 41.715 ;
     RECT  2.16 41.985 49.68 42.255 ;
     RECT  2.16 42.525 49.68 42.795 ;
     RECT  2.16 43.065 49.68 43.335 ;
     RECT  2.16 43.605 49.68 43.875 ;
     RECT  2.16 44.145 49.68 44.415 ;
     RECT  2.16 44.685 49.68 44.955 ;
     RECT  2.16 45.225 49.68 45.495 ;
     RECT  2.16 45.765 49.68 46.035 ;
     RECT  2.16 46.305 49.68 46.575 ;
     RECT  2.16 46.845 49.68 47.115 ;
     RECT  2.16 47.385 49.68 47.655 ;
     RECT  2.16 47.925 49.68 48.195 ;
     RECT  2.16 48.465 49.68 48.735 ;
     RECT  2.16 49.005 49.68 49.275 ;
     RECT  2.16 49.545 49.68 49.68 ;
    LAYER RVTP ;
     RECT  2.16 2.295 49.68 2.565 ;
     RECT  2.16 2.835 49.68 3.105 ;
     RECT  2.16 3.375 49.68 3.645 ;
     RECT  2.16 3.915 49.68 4.185 ;
     RECT  2.16 4.455 49.68 4.725 ;
     RECT  2.16 4.995 49.68 5.265 ;
     RECT  2.16 5.535 49.68 5.805 ;
     RECT  2.16 6.075 49.68 6.345 ;
     RECT  2.16 6.615 49.68 6.885 ;
     RECT  2.16 7.155 49.68 7.425 ;
     RECT  2.16 7.695 49.68 7.965 ;
     RECT  2.16 8.235 49.68 8.505 ;
     RECT  2.16 8.775 49.68 9.045 ;
     RECT  2.16 9.315 49.68 9.585 ;
     RECT  2.16 9.855 49.68 10.125 ;
     RECT  2.16 10.395 49.68 10.665 ;
     RECT  2.16 10.935 49.68 11.205 ;
     RECT  2.16 11.475 49.68 11.745 ;
     RECT  2.16 12.015 49.68 12.285 ;
     RECT  2.16 12.555 49.68 12.825 ;
     RECT  2.16 13.095 49.68 13.365 ;
     RECT  2.16 13.635 49.68 13.905 ;
     RECT  2.16 14.175 49.68 14.445 ;
     RECT  2.16 14.715 49.68 14.985 ;
     RECT  2.16 15.255 49.68 15.525 ;
     RECT  2.16 15.795 49.68 16.065 ;
     RECT  2.16 16.335 49.68 16.605 ;
     RECT  2.16 16.875 49.68 17.145 ;
     RECT  2.16 17.415 49.68 17.685 ;
     RECT  2.16 17.955 49.68 18.225 ;
     RECT  2.16 18.495 49.68 18.765 ;
     RECT  2.16 19.035 49.68 19.305 ;
     RECT  2.16 19.575 49.68 19.845 ;
     RECT  2.16 20.115 49.68 20.385 ;
     RECT  2.16 20.655 49.68 20.925 ;
     RECT  2.16 21.195 49.68 21.465 ;
     RECT  2.16 21.735 49.68 22.005 ;
     RECT  2.16 22.275 49.68 22.545 ;
     RECT  2.16 22.815 49.68 23.085 ;
     RECT  2.16 23.355 49.68 23.625 ;
     RECT  2.16 23.895 49.68 24.165 ;
     RECT  2.16 24.435 49.68 24.705 ;
     RECT  2.16 24.975 49.68 25.245 ;
     RECT  2.16 25.515 49.68 25.785 ;
     RECT  2.16 26.055 49.68 26.325 ;
     RECT  2.16 26.595 49.68 26.865 ;
     RECT  2.16 27.135 49.68 27.405 ;
     RECT  2.16 27.675 49.68 27.945 ;
     RECT  2.16 28.215 49.68 28.485 ;
     RECT  2.16 28.755 49.68 29.025 ;
     RECT  2.16 29.295 49.68 29.565 ;
     RECT  2.16 29.835 49.68 30.105 ;
     RECT  2.16 30.375 49.68 30.645 ;
     RECT  2.16 30.915 49.68 31.185 ;
     RECT  2.16 31.455 49.68 31.725 ;
     RECT  2.16 31.995 49.68 32.265 ;
     RECT  2.16 32.535 49.68 32.805 ;
     RECT  2.16 33.075 49.68 33.345 ;
     RECT  2.16 33.615 49.68 33.885 ;
     RECT  2.16 34.155 49.68 34.425 ;
     RECT  2.16 34.695 49.68 34.965 ;
     RECT  2.16 35.235 49.68 35.505 ;
     RECT  2.16 35.775 49.68 36.045 ;
     RECT  2.16 36.315 49.68 36.585 ;
     RECT  2.16 36.855 49.68 37.125 ;
     RECT  2.16 37.395 49.68 37.665 ;
     RECT  2.16 37.935 49.68 38.205 ;
     RECT  2.16 38.475 49.68 38.745 ;
     RECT  2.16 39.015 49.68 39.285 ;
     RECT  2.16 39.555 49.68 39.825 ;
     RECT  2.16 40.095 49.68 40.365 ;
     RECT  2.16 40.635 49.68 40.905 ;
     RECT  2.16 41.175 49.68 41.445 ;
     RECT  2.16 41.715 49.68 41.985 ;
     RECT  2.16 42.255 49.68 42.525 ;
     RECT  2.16 42.795 49.68 43.065 ;
     RECT  2.16 43.335 49.68 43.605 ;
     RECT  2.16 43.875 49.68 44.145 ;
     RECT  2.16 44.415 49.68 44.685 ;
     RECT  2.16 44.955 49.68 45.225 ;
     RECT  2.16 45.495 49.68 45.765 ;
     RECT  2.16 46.035 49.68 46.305 ;
     RECT  2.16 46.575 49.68 46.845 ;
     RECT  2.16 47.115 49.68 47.385 ;
     RECT  2.16 47.655 49.68 47.925 ;
     RECT  2.16 48.195 49.68 48.465 ;
     RECT  2.16 48.735 49.68 49.005 ;
     RECT  2.16 49.275 49.68 49.545 ;
    LAYER M1 ;
     RECT  2.16 2.151 49.68 49.689 ;
    LAYER M2 ;
     RECT  0.103 19.656 0.139 19.674 ;
     RECT  0.103 21.006 0.139 21.492 ;
     RECT  0.103 14.796 0.203 14.814 ;
     RECT  0.103 15.804 0.203 15.822 ;
     RECT  0.103 23.292 0.239 23.31 ;
     RECT  0.103 24.714 0.347 24.966 ;
     RECT  0.139 19.656 0.463 21.654 ;
     RECT  0.103 13.068 0.535 13.086 ;
     RECT  0.463 19.386 0.535 21.654 ;
     RECT  0.499 22.482 0.535 22.5 ;
     RECT  0.499 43.146 0.535 43.164 ;
     RECT  0.535 19.35 1.175 22.572 ;
     RECT  0.535 13.068 2.16 13.392 ;
     RECT  1.175 19.35 2.16 19.602 ;
     RECT  1.175 20.394 2.16 22.572 ;
     RECT  0.103 26.406 2.16 26.424 ;
     RECT  0.535 43.146 2.16 43.866 ;
     RECT  11.407 51.606 11.507 51.624 ;
     RECT  2.16 2.151 13.999 49.689 ;
     RECT  13.999 2.106 16.979 49.689 ;
     RECT  16.979 2.151 49.68 49.689 ;
     RECT  49.68 13.95 49.739 15.588 ;
     RECT  49.68 44.424 50.171 46.674 ;
     RECT  49.68 7.236 50.531 9.684 ;
     RECT  49.68 32.004 50.683 32.022 ;
     RECT  49.739 13.986 50.711 15.588 ;
     RECT  50.683 31.932 50.711 32.022 ;
     RECT  49.68 13.14 50.747 13.158 ;
     RECT  50.711 13.986 50.747 15.516 ;
     RECT  49.68 21.438 50.747 23.184 ;
     RECT  49.68 25.794 50.747 29.358 ;
     RECT  50.171 44.424 50.747 45.324 ;
     RECT  50.171 46.116 50.747 46.674 ;
     RECT  49.68 12.096 50.783 12.348 ;
     RECT  50.747 21.438 50.783 23.148 ;
     RECT  50.747 25.866 50.783 27.504 ;
     RECT  50.783 22.554 50.819 23.148 ;
     RECT  50.783 26.064 50.819 27.504 ;
     RECT  50.747 44.496 50.819 45.324 ;
     RECT  50.819 22.554 50.855 22.914 ;
     RECT  50.819 44.496 50.855 44.514 ;
     RECT  50.855 22.626 50.891 22.914 ;
     RECT  50.891 22.626 50.963 22.878 ;
     RECT  50.531 9.126 51.287 9.684 ;
     RECT  51.287 9.126 51.359 9.144 ;
     RECT  50.531 7.236 51.431 8.334 ;
     RECT  51.431 7.236 51.503 8.028 ;
     RECT  51.439 10.908 51.511 10.926 ;
     RECT  50.747 46.386 51.511 46.674 ;
     RECT  51.503 7.236 51.575 7.524 ;
     RECT  50.747 14.031 51.575 15.516 ;
     RECT  50.747 28.728 51.575 29.358 ;
     RECT  51.575 14.49 51.611 15.516 ;
     RECT  50.783 21.438 51.619 21.528 ;
     RECT  51.575 28.728 51.619 28.746 ;
     RECT  51.575 7.236 51.647 7.488 ;
     RECT  51.511 10.836 51.647 10.926 ;
     RECT  50.819 45.306 51.655 45.324 ;
     RECT  49.68 24.786 51.683 24.804 ;
     RECT  51.511 46.242 51.683 46.674 ;
     RECT  51.647 7.236 51.719 7.254 ;
     RECT  51.647 10.836 51.719 10.854 ;
     RECT  51.619 21.096 51.719 21.528 ;
     RECT  51.683 46.656 51.719 46.674 ;
     RECT  50.963 22.86 51.727 22.878 ;
     RECT  51.619 28.422 51.727 28.746 ;
     RECT  51.611 14.652 51.755 15.129 ;
     RECT  51.719 21.096 51.755 21.114 ;
     RECT  51.727 22.86 51.755 23.382 ;
     RECT  50.819 26.064 51.755 26.694 ;
     RECT  50.819 27.486 51.755 27.504 ;
     RECT  51.727 28.296 51.755 28.746 ;
     RECT  51.655 44.892 51.755 45.324 ;
     RECT  49.68 5.616 51.791 5.634 ;
     RECT  51.691 13.176 51.791 13.194 ;
     RECT  50.783 12.33 51.827 12.348 ;
     RECT  51.755 23.364 51.827 23.382 ;
     RECT  51.755 28.296 51.827 28.314 ;
     RECT  50.711 31.932 51.827 31.95 ;
    LAYER M3 ;
     RECT  14.004 2.101 14.022 2.143 ;
     RECT  16.524 2.101 16.974 2.143 ;
     RECT  5.115 2.143 5.205 2.191 ;
     RECT  15.915 2.143 16.974 2.191 ;
     RECT  18.615 2.143 18.705 2.191 ;
     RECT  21.315 2.143 21.405 2.191 ;
     RECT  26.715 2.143 26.805 2.191 ;
     RECT  29.415 2.143 29.505 2.191 ;
     RECT  34.815 2.143 34.905 2.191 ;
     RECT  40.215 2.143 40.305 2.191 ;
     RECT  24.015 2.143 24.105 2.227 ;
     RECT  40.215 2.191 40.734 2.227 ;
     RECT  45.615 2.143 45.705 2.227 ;
     RECT  18.324 2.191 18.705 2.251 ;
     RECT  19.476 2.191 19.494 2.251 ;
     RECT  29.415 2.191 29.79 2.251 ;
     RECT  30.636 2.191 30.654 2.251 ;
     RECT  32.115 2.143 32.205 2.251 ;
     RECT  43.74 2.227 43.758 2.251 ;
     RECT  44.748 2.227 44.766 2.251 ;
     RECT  45.615 2.227 45.846 2.251 ;
     RECT  5.115 2.191 5.274 2.263 ;
     RECT  25.668 2.191 26.805 2.263 ;
     RECT  27.972 2.191 27.99 2.263 ;
     RECT  29.415 2.251 30.654 2.263 ;
     RECT  38.376 2.227 38.394 2.263 ;
     RECT  43.74 2.251 45.846 2.263 ;
     RECT  46.8 2.191 46.818 2.263 ;
     RECT  4.716 2.263 5.274 2.299 ;
     RECT  6.984 2.227 7.002 2.299 ;
     RECT  12.384 2.251 12.402 2.299 ;
     RECT  13.215 2.143 14.022 2.299 ;
     RECT  15.804 2.191 16.974 2.299 ;
     RECT  18.324 2.251 19.962 2.299 ;
     RECT  24.015 2.227 24.174 2.299 ;
     RECT  25.668 2.263 27.99 2.299 ;
     RECT  29.376 2.263 30.654 2.299 ;
     RECT  31.716 2.251 32.205 2.299 ;
     RECT  33.876 2.191 33.894 2.299 ;
     RECT  34.815 2.191 35.442 2.299 ;
     RECT  43.74 2.263 46.962 2.299 ;
     RECT  3.672 2.299 3.69 2.335 ;
     RECT  9.684 2.191 9.702 2.335 ;
     RECT  21.24 2.191 21.405 2.335 ;
     RECT  24.015 2.299 24.39 2.335 ;
     RECT  25.632 2.299 27.99 2.335 ;
     RECT  33.876 2.299 35.694 2.335 ;
     RECT  36.612 2.191 36.63 2.335 ;
     RECT  3.672 2.335 3.87 2.371 ;
     RECT  4.716 2.299 5.742 2.371 ;
     RECT  6.84 2.299 7.002 2.371 ;
     RECT  8.712 2.251 8.73 2.371 ;
     RECT  9.576 2.335 9.702 2.371 ;
     RECT  15.804 2.299 20.358 2.371 ;
     RECT  22.392 2.227 22.41 2.371 ;
     RECT  29.376 2.299 32.205 2.371 ;
     RECT  37.515 2.143 37.605 2.371 ;
     RECT  38.376 2.263 38.538 2.371 ;
     RECT  39.564 2.227 40.986 2.371 ;
     RECT  42.048 2.227 42.066 2.371 ;
     RECT  2.415 2.143 2.505 2.413 ;
     RECT  7.815 2.143 7.905 2.413 ;
     RECT  8.712 2.371 9.702 2.413 ;
     RECT  10.515 2.143 10.605 2.413 ;
     RECT  21.24 2.335 21.474 2.413 ;
     RECT  42.915 2.143 43.005 2.413 ;
     RECT  43.74 2.299 47.106 2.413 ;
     RECT  48.315 2.143 48.405 2.413 ;
     RECT  3.672 2.371 5.742 2.461 ;
     RECT  21.24 2.413 21.597 2.461 ;
     RECT  22.392 2.371 22.518 2.461 ;
     RECT  29.376 2.371 32.454 2.461 ;
     RECT  33.84 2.335 36.63 2.461 ;
     RECT  37.476 2.371 42.066 2.461 ;
     RECT  42.915 2.413 47.106 2.461 ;
     RECT  15.732 2.371 20.394 2.491 ;
     RECT  21.24 2.461 22.518 2.491 ;
     RECT  24.015 2.335 27.99 2.491 ;
     RECT  33.3 2.461 36.63 2.497 ;
     RECT  37.476 2.461 47.214 2.497 ;
     RECT  12.384 2.299 14.022 2.569 ;
     RECT  29.088 2.461 32.454 2.569 ;
     RECT  33.3 2.497 47.214 2.569 ;
     RECT  2.415 2.413 2.697 2.605 ;
     RECT  3.672 2.461 5.814 2.605 ;
     RECT  6.732 2.371 7.002 2.605 ;
     RECT  7.815 2.413 9.702 2.605 ;
     RECT  10.515 2.413 10.797 2.605 ;
     RECT  15.732 2.491 22.518 2.641 ;
     RECT  23.4 2.491 27.99 2.641 ;
     RECT  29.088 2.569 47.214 2.641 ;
     RECT  2.415 2.605 11.178 2.767 ;
     RECT  2.376 2.767 11.178 2.803 ;
     RECT  12.384 2.569 14.526 2.803 ;
     RECT  15.732 2.641 47.214 2.839 ;
     RECT  2.376 2.803 14.526 2.875 ;
     RECT  15.264 2.839 47.214 2.875 ;
     RECT  48.315 2.413 48.597 2.875 ;
     RECT  2.376 2.875 48.597 2.911 ;
     RECT  49.5 2.641 49.518 2.911 ;
     RECT  2.376 2.911 49.518 3.443 ;
     RECT  2.376 3.443 11.394 3.947 ;
     RECT  12.456 3.443 49.518 4.109 ;
     RECT  15.372 4.109 49.518 4.145 ;
     RECT  15.372 4.145 17.694 4.181 ;
     RECT  2.376 3.947 11.322 4.379 ;
     RECT  2.415 4.379 11.322 4.721 ;
     RECT  2.415 4.721 8.154 4.829 ;
     RECT  9.144 4.721 11.322 5.071 ;
     RECT  12.456 4.109 14.526 5.071 ;
     RECT  15.372 4.181 17.442 5.071 ;
     RECT  18.504 4.145 49.518 5.071 ;
     RECT  12.456 5.071 49.518 5.197 ;
     RECT  12.42 5.197 49.518 5.305 ;
     RECT  2.415 4.829 8.097 5.575 ;
     RECT  9.144 5.071 11.394 5.575 ;
     RECT  12.168 5.305 49.518 5.611 ;
     RECT  2.415 5.575 11.394 5.737 ;
     RECT  12.132 5.611 49.518 5.737 ;
     RECT  2.415 5.737 49.518 6.691 ;
     RECT  2.415 6.691 49.554 6.845 ;
     RECT  2.415 6.845 33.174 6.917 ;
     RECT  2.415 6.917 33.138 6.989 ;
     RECT  2.415 6.989 33.102 7.181 ;
     RECT  51.768 5.611 51.786 7.231 ;
     RECT  2.415 7.181 33.066 7.259 ;
     RECT  34.02 6.845 49.518 7.385 ;
     RECT  51.696 7.231 51.786 7.465 ;
     RECT  51.624 7.465 51.786 7.501 ;
     RECT  2.415 7.259 32.994 7.591 ;
     RECT  36.36 7.385 49.518 7.771 ;
     RECT  51.552 7.501 51.786 8.005 ;
     RECT  34.02 7.385 35.55 8.155 ;
     RECT  2.376 7.591 32.994 8.167 ;
     RECT  33.948 8.155 35.55 8.167 ;
     RECT  51.48 8.005 51.786 8.311 ;
     RECT  2.376 8.167 35.55 8.473 ;
     RECT  36.36 7.771 49.878 8.473 ;
     RECT  2.376 8.473 50.454 8.509 ;
     RECT  2.34 8.509 50.526 8.969 ;
     RECT  51.408 8.311 51.786 9.121 ;
     RECT  2.34 8.969 33.39 9.347 ;
     RECT  2.34 9.347 33.318 9.509 ;
     RECT  51.336 9.121 51.786 9.661 ;
     RECT  34.236 8.969 50.526 9.823 ;
     RECT  34.2 9.823 50.526 10.123 ;
     RECT  51.264 9.661 51.786 10.123 ;
     RECT  34.2 10.123 51.786 10.291 ;
     RECT  2.376 9.509 33.318 10.355 ;
     RECT  2.415 10.355 33.318 10.471 ;
     RECT  2.415 10.471 33.354 10.741 ;
     RECT  34.128 10.291 51.786 10.741 ;
     RECT  2.415 10.741 51.786 10.859 ;
     RECT  34.2 10.859 51.786 11.741 ;
     RECT  2.415 10.859 33.426 11.821 ;
     RECT  34.2 11.741 44.118 11.821 ;
     RECT  45.108 11.741 51.786 12.325 ;
     RECT  2.415 11.821 44.118 12.487 ;
     RECT  2.412 12.487 44.118 12.587 ;
     RECT  34.776 12.587 44.118 12.595 ;
     RECT  45.108 12.325 51.822 12.595 ;
     RECT  2.412 12.587 33.93 12.901 ;
     RECT  2.376 12.901 33.93 13.333 ;
     RECT  0.108 13.063 0.126 13.369 ;
     RECT  2.34 13.333 33.93 13.369 ;
     RECT  34.776 12.595 51.822 13.369 ;
     RECT  2.34 13.369 51.822 13.441 ;
     RECT  0.108 13.369 0.558 13.805 ;
     RECT  2.304 13.441 51.822 14.093 ;
     RECT  2.34 14.093 51.822 14.099 ;
     RECT  46.656 14.099 51.822 14.135 ;
     RECT  2.34 14.099 45.897 14.141 ;
     RECT  2.34 14.141 3.258 14.171 ;
     RECT  0.18 13.805 0.558 14.285 ;
     RECT  0.18 14.285 0.198 14.539 ;
     RECT  46.692 14.135 51.822 14.573 ;
     RECT  0.108 14.539 0.198 14.828 ;
     RECT  4.104 14.141 45.897 14.881 ;
     RECT  46.692 14.573 50.526 14.881 ;
     RECT  4.104 14.881 50.526 14.909 ;
     RECT  2.415 14.171 3.258 14.989 ;
     RECT  0.144 14.828 0.162 15.005 ;
     RECT  2.268 14.989 3.258 15.149 ;
     RECT  2.304 15.149 3.258 15.151 ;
     RECT  4.104 14.909 36.054 15.151 ;
     RECT  51.372 14.573 51.822 15.521 ;
     RECT  36.936 14.909 50.526 15.565 ;
     RECT  36.936 15.565 50.706 15.629 ;
     RECT  36.936 15.629 50.526 15.725 ;
     RECT  36.936 15.725 50.454 15.821 ;
     RECT  0.108 15.799 0.198 15.869 ;
     RECT  2.304 15.151 36.054 15.871 ;
     RECT  36.936 15.821 49.374 15.871 ;
     RECT  0.108 15.869 0.126 15.917 ;
     RECT  2.304 15.871 49.374 15.917 ;
     RECT  50.436 15.821 50.454 16.013 ;
     RECT  2.304 15.917 49.122 16.168 ;
     RECT  2.268 16.168 49.122 16.259 ;
     RECT  2.268 16.259 37.797 16.304 ;
     RECT  2.268 16.304 22.914 16.331 ;
     RECT  23.652 16.304 37.797 16.367 ;
     RECT  2.304 16.331 22.914 16.529 ;
     RECT  23.652 16.367 28.278 16.529 ;
     RECT  38.772 16.259 49.122 16.552 ;
     RECT  29.052 16.367 37.797 16.733 ;
     RECT  2.415 16.529 22.914 16.799 ;
     RECT  38.916 16.552 49.122 16.915 ;
     RECT  3.888 16.799 22.914 17.113 ;
     RECT  23.652 16.529 25.074 17.113 ;
     RECT  2.415 16.799 3.006 17.339 ;
     RECT  38.916 16.915 49.194 17.347 ;
     RECT  25.884 16.529 28.278 17.383 ;
     RECT  29.052 16.733 29.697 17.383 ;
     RECT  3.888 17.113 25.074 17.491 ;
     RECT  25.884 17.383 29.697 17.491 ;
     RECT  30.492 16.733 37.797 17.491 ;
     RECT  38.88 17.347 49.194 17.491 ;
     RECT  3.888 17.491 37.797 17.581 ;
     RECT  38.88 17.491 49.302 17.609 ;
     RECT  3.672 17.581 37.797 17.645 ;
     RECT  38.88 17.609 38.97 17.689 ;
     RECT  3.996 17.645 37.797 17.761 ;
     RECT  38.556 17.689 38.97 17.761 ;
     RECT  39.852 17.609 49.302 17.761 ;
     RECT  3.996 17.761 38.97 17.879 ;
     RECT  39.852 17.761 49.41 18.221 ;
     RECT  4.14 17.879 38.97 18.571 ;
     RECT  39.852 18.221 49.23 18.571 ;
     RECT  2.415 17.339 2.697 18.661 ;
     RECT  4.14 18.571 49.23 18.769 ;
     RECT  4.068 18.769 49.23 18.995 ;
     RECT  4.068 18.995 49.158 19.031 ;
     RECT  4.068 19.031 23.058 19.039 ;
     RECT  3.888 19.039 23.058 19.067 ;
     RECT  2.415 18.661 3.042 19.111 ;
     RECT  3.888 19.067 22.806 19.111 ;
     RECT  23.94 19.031 49.158 19.229 ;
     RECT  23.94 19.229 49.086 19.265 ;
     RECT  0.54 19.345 0.558 19.381 ;
     RECT  2.415 19.111 22.806 19.471 ;
     RECT  2.376 19.471 22.806 19.507 ;
     RECT  0.468 19.381 0.558 19.543 ;
     RECT  0.468 19.543 1.17 19.651 ;
     RECT  2.268 19.507 22.806 19.841 ;
     RECT  23.94 19.265 49.05 19.853 ;
     RECT  2.304 19.841 22.806 19.867 ;
     RECT  2.304 19.867 22.878 19.949 ;
     RECT  23.94 19.853 36.774 19.949 ;
     RECT  23.94 19.949 36.702 20.119 ;
     RECT  2.415 19.949 22.878 20.191 ;
     RECT  23.616 20.119 36.702 20.191 ;
     RECT  37.515 19.853 49.05 20.191 ;
     RECT  37.515 20.191 49.122 20.317 ;
     RECT  37.515 20.317 49.41 20.425 ;
     RECT  0.108 19.651 1.17 20.525 ;
     RECT  37.515 20.425 49.554 20.849 ;
     RECT  2.415 20.191 36.702 21.001 ;
     RECT  37.515 20.849 49.41 21.001 ;
     RECT  0.108 20.525 0.594 21.101 ;
     RECT  2.415 21.001 49.41 21.119 ;
     RECT  37.476 21.119 49.41 21.389 ;
     RECT  51.588 15.521 51.822 21.433 ;
     RECT  2.415 21.119 36.666 21.541 ;
     RECT  2.304 21.541 36.666 21.569 ;
     RECT  0.108 21.101 0.558 21.677 ;
     RECT  50.904 21.433 51.822 21.811 ;
     RECT  37.476 21.389 49.086 21.901 ;
     RECT  0.144 21.677 0.558 21.965 ;
     RECT  3.78 21.569 36.666 22.009 ;
     RECT  37.44 21.901 49.086 22.009 ;
     RECT  50.76 21.811 51.822 22.081 ;
     RECT  0.252 21.965 0.558 22.157 ;
     RECT  3.78 22.009 49.086 22.351 ;
     RECT  2.304 21.569 2.697 22.441 ;
     RECT  3.78 22.351 49.194 22.441 ;
     RECT  0.504 22.157 0.558 22.459 ;
     RECT  0.504 22.459 0.594 22.507 ;
     RECT  0.504 22.507 0.666 22.637 ;
     RECT  0.504 22.637 0.558 22.925 ;
     RECT  2.304 22.441 49.194 22.981 ;
     RECT  2.304 22.981 49.302 23.089 ;
     RECT  2.304 23.089 49.482 23.189 ;
     RECT  0.324 23.179 0.342 23.275 ;
     RECT  0.108 23.275 0.342 23.309 ;
     RECT  50.724 22.081 51.822 23.309 ;
     RECT  0.108 23.309 0.234 23.315 ;
     RECT  0.216 23.315 0.234 23.357 ;
     RECT  50.76 23.309 51.822 23.387 ;
     RECT  50.76 23.387 51.75 23.405 ;
     RECT  15.768 23.189 49.482 23.549 ;
     RECT  50.76 23.405 51.714 23.789 ;
     RECT  50.796 23.789 51.714 23.885 ;
     RECT  1.152 23.755 1.17 23.933 ;
     RECT  2.304 23.189 14.922 23.935 ;
     RECT  15.768 23.549 49.122 23.935 ;
     RECT  50.832 23.885 51.714 23.981 ;
     RECT  50.868 23.981 51.714 24.077 ;
     RECT  0.144 24.043 0.162 24.139 ;
     RECT  50.904 24.077 51.714 24.173 ;
     RECT  0.144 24.139 0.234 24.331 ;
     RECT  50.904 24.173 51.678 24.365 ;
     RECT  0.144 24.331 0.342 24.619 ;
     RECT  50.94 24.365 51.678 24.653 ;
     RECT  0.108 24.619 0.342 24.907 ;
     RECT  2.304 23.935 49.122 24.935 ;
     RECT  0.108 24.907 0.414 25.085 ;
     RECT  51.336 24.653 51.678 25.133 ;
     RECT  31.644 24.935 49.05 25.619 ;
     RECT  19.908 24.935 30.906 25.675 ;
     RECT  31.644 25.619 41.67 25.675 ;
     RECT  2.304 24.935 18.954 25.753 ;
     RECT  19.908 25.675 41.67 25.753 ;
     RECT  0.108 25.085 0.162 25.805 ;
     RECT  51.516 25.133 51.678 25.805 ;
     RECT  42.66 25.619 49.05 25.825 ;
     RECT  50.724 25.789 50.742 25.861 ;
     RECT  51.588 25.805 51.678 25.997 ;
     RECT  51.624 25.997 51.678 26.059 ;
     RECT  42.66 25.825 49.374 26.095 ;
     RECT  50.724 25.861 50.778 26.131 ;
     RECT  50.724 26.131 50.85 26.155 ;
     RECT  2.304 25.753 41.67 26.159 ;
     RECT  2.376 26.159 41.67 26.249 ;
     RECT  42.66 26.095 49.626 26.251 ;
     RECT  50.652 26.155 50.85 26.251 ;
     RECT  2.415 26.249 41.67 26.365 ;
     RECT  42.66 26.251 50.85 26.365 ;
     RECT  2.415 26.365 50.85 26.381 ;
     RECT  50.148 26.381 50.85 26.393 ;
     RECT  0.108 25.805 0.126 26.429 ;
     RECT  2.415 26.381 49.266 26.789 ;
     RECT  51.624 26.059 51.75 26.861 ;
     RECT  34.092 26.789 49.266 26.897 ;
     RECT  50.724 26.393 50.85 26.957 ;
     RECT  2.415 26.789 33.282 26.969 ;
     RECT  2.415 26.969 33.246 27.329 ;
     RECT  50.724 26.957 50.814 27.341 ;
     RECT  34.524 26.897 49.266 27.409 ;
     RECT  51.732 26.861 51.75 27.509 ;
     RECT  34.524 27.409 49.302 27.751 ;
     RECT  34.272 27.751 49.302 27.913 ;
     RECT  50.724 27.341 50.742 27.979 ;
     RECT  34.056 27.913 49.302 28.075 ;
     RECT  2.415 27.329 33.21 28.147 ;
     RECT  2.415 28.147 33.246 28.219 ;
     RECT  51.552 28.171 51.678 28.267 ;
     RECT  34.056 28.075 49.59 28.283 ;
     RECT  51.552 28.267 51.75 28.291 ;
     RECT  50.652 27.979 50.742 28.481 ;
     RECT  50.724 28.481 50.742 28.493 ;
     RECT  51.552 28.291 51.822 28.507 ;
     RECT  2.415 28.219 33.318 28.651 ;
     RECT  34.056 28.283 49.266 28.651 ;
     RECT  51.516 28.507 51.822 28.747 ;
     RECT  2.415 28.651 49.266 28.831 ;
     RECT  51.408 28.747 51.822 28.877 ;
     RECT  51.552 28.877 51.822 29.363 ;
     RECT  2.376 28.831 49.266 31.019 ;
     RECT  2.415 31.019 49.266 31.145 ;
     RECT  2.415 31.145 35.766 31.915 ;
     RECT  36.504 31.145 49.266 31.915 ;
     RECT  51.804 29.363 51.822 31.955 ;
     RECT  50.688 31.927 50.706 32.027 ;
     RECT  2.415 31.915 49.266 32.071 ;
     RECT  2.415 32.071 49.482 32.567 ;
     RECT  2.415 32.567 49.446 33.007 ;
     RECT  2.376 33.007 49.446 33.269 ;
     RECT  2.376 33.269 49.374 33.539 ;
     RECT  2.415 33.539 49.374 34.465 ;
     RECT  2.415 34.465 49.446 34.655 ;
     RECT  7.452 34.655 49.446 34.889 ;
     RECT  2.415 34.655 6.714 35.311 ;
     RECT  7.452 34.889 49.374 35.429 ;
     RECT  2.34 35.311 6.714 35.545 ;
     RECT  7.452 35.429 22.23 35.545 ;
     RECT  2.34 35.545 22.23 35.699 ;
     RECT  23.256 35.429 49.374 35.807 ;
     RECT  2.34 35.699 21.87 36.005 ;
     RECT  23.256 35.807 49.266 36.239 ;
     RECT  2.415 36.005 21.87 36.419 ;
     RECT  36.684 36.239 49.266 36.851 ;
     RECT  23.256 36.239 35.946 36.959 ;
     RECT  36.684 36.851 49.194 37.049 ;
     RECT  2.415 36.419 21.798 37.085 ;
     RECT  34.488 36.959 35.946 37.165 ;
     RECT  36.684 37.049 41.094 37.165 ;
     RECT  34.488 37.165 41.094 37.499 ;
     RECT  23.256 36.959 33.606 37.741 ;
     RECT  34.488 37.499 39.366 37.741 ;
     RECT  9.684 37.085 21.798 37.831 ;
     RECT  40.215 37.499 41.094 37.903 ;
     RECT  41.868 37.049 49.194 37.903 ;
     RECT  2.415 37.085 8.802 38.011 ;
     RECT  9.684 37.831 21.906 38.011 ;
     RECT  2.415 38.011 22.122 38.101 ;
     RECT  2.376 38.101 22.122 38.189 ;
     RECT  40.215 37.903 49.194 38.281 ;
     RECT  2.415 38.189 22.122 38.395 ;
     RECT  23.256 37.741 39.366 38.395 ;
     RECT  40.176 38.281 49.23 38.435 ;
     RECT  2.415 38.395 39.366 38.479 ;
     RECT  40.176 38.435 49.194 38.479 ;
     RECT  2.415 38.479 49.194 39.325 ;
     RECT  2.415 39.325 49.23 39.479 ;
     RECT  2.415 39.479 39.15 39.551 ;
     RECT  2.415 39.551 38.898 39.857 ;
     RECT  9.792 39.857 38.898 40.325 ;
     RECT  34.236 40.325 38.898 40.441 ;
     RECT  40.104 39.479 49.05 40.441 ;
     RECT  2.415 39.857 9.018 40.603 ;
     RECT  9.792 40.325 33.462 40.603 ;
     RECT  2.415 40.603 33.462 41.071 ;
     RECT  34.236 40.441 49.05 41.071 ;
     RECT  2.415 41.071 49.05 41.215 ;
     RECT  2.415 41.215 49.374 41.369 ;
     RECT  2.415 41.369 49.302 41.945 ;
     RECT  2.415 41.945 49.194 42.179 ;
     RECT  28.8 42.179 49.014 42.251 ;
     RECT  28.8 42.251 48.834 42.269 ;
     RECT  28.872 42.269 48.834 42.863 ;
     RECT  2.415 42.179 27.738 43.105 ;
     RECT  28.872 42.863 41.994 43.105 ;
     RECT  42.915 42.863 48.834 43.141 ;
     RECT  0.504 43.141 0.522 43.303 ;
     RECT  42.915 43.141 49.338 43.375 ;
     RECT  42.915 43.375 49.482 43.529 ;
     RECT  42.915 43.529 49.338 43.565 ;
     RECT  0.504 43.303 0.558 43.661 ;
     RECT  2.415 43.105 41.994 43.681 ;
     RECT  42.915 43.565 49.23 43.681 ;
     RECT  0.54 43.661 0.558 44.045 ;
     RECT  2.304 43.681 49.23 44.155 ;
     RECT  2.196 44.155 49.23 44.333 ;
     RECT  2.304 44.333 49.23 44.375 ;
     RECT  50.724 44.419 50.742 44.491 ;
     RECT  2.304 44.375 49.194 44.753 ;
     RECT  2.304 44.753 27.126 44.789 ;
     RECT  51.732 44.875 51.75 44.887 ;
     RECT  51.66 44.887 51.75 44.957 ;
     RECT  0.144 44.779 0.162 45.067 ;
     RECT  50.724 44.491 50.85 45.101 ;
     RECT  27.972 44.753 49.194 45.149 ;
     RECT  0.144 45.067 0.342 45.163 ;
     RECT  0.108 45.163 0.342 45.197 ;
     RECT  50.724 45.101 50.814 45.256 ;
     RECT  51.732 44.957 51.75 45.329 ;
     RECT  0.108 45.197 0.126 45.485 ;
     RECT  27.972 45.149 49.158 45.931 ;
     RECT  50.148 45.256 50.814 45.931 ;
     RECT  2.376 44.789 27.126 45.959 ;
     RECT  27.864 45.931 49.158 45.959 ;
     RECT  50.076 45.931 50.814 46.031 ;
     RECT  7.488 45.959 27.126 46.039 ;
     RECT  27.864 45.959 48.762 46.039 ;
     RECT  2.376 45.959 6.714 46.219 ;
     RECT  50.148 46.031 50.814 46.237 ;
     RECT  51.552 46.219 51.678 46.237 ;
     RECT  50.148 46.237 51.678 46.315 ;
     RECT  50.148 46.315 51.714 46.349 ;
     RECT  51.552 46.349 51.714 46.445 ;
     RECT  50.148 46.349 50.814 46.541 ;
     RECT  7.488 46.039 48.762 46.571 ;
     RECT  50.148 46.541 50.742 46.571 ;
     RECT  51.696 46.445 51.714 46.679 ;
     RECT  50.724 46.571 50.742 46.733 ;
     RECT  19.944 46.571 48.762 46.921 ;
     RECT  19.944 46.921 49.014 47.075 ;
     RECT  20.088 47.075 49.014 47.147 ;
     RECT  2.34 46.219 6.714 47.191 ;
     RECT  7.488 46.571 19.206 47.191 ;
     RECT  34.092 47.147 49.014 47.191 ;
     RECT  20.088 47.147 33.318 47.579 ;
     RECT  20.196 47.579 33.318 47.947 ;
     RECT  34.092 47.191 49.158 47.947 ;
     RECT  20.196 47.947 49.158 47.965 ;
     RECT  20.196 47.965 49.554 48.119 ;
     RECT  2.34 47.191 19.206 48.361 ;
     RECT  20.196 48.119 48.834 48.361 ;
     RECT  2.34 48.361 48.834 48.533 ;
     RECT  39.42 48.533 48.834 48.659 ;
     RECT  2.34 48.533 38.61 48.701 ;
     RECT  2.34 48.701 25.254 48.803 ;
     RECT  25.992 48.701 38.61 48.803 ;
     RECT  2.34 48.803 25.074 48.839 ;
     RECT  19.728 48.839 25.074 48.929 ;
     RECT  25.992 48.803 31.194 48.929 ;
     RECT  39.42 48.659 48.69 48.929 ;
     RECT  2.34 48.839 18.99 48.965 ;
     RECT  2.415 48.965 18.99 49.001 ;
     RECT  32.004 48.803 38.61 49.037 ;
     RECT  9.36 49.001 18.99 49.199 ;
     RECT  19.728 48.929 24.822 49.199 ;
     RECT  26.1 48.929 31.194 49.199 ;
     RECT  32.004 49.037 36.09 49.199 ;
     RECT  39.42 48.929 48.597 49.199 ;
     RECT  2.415 49.001 8.514 49.235 ;
     RECT  20.988 49.199 24.822 49.235 ;
     RECT  26.1 49.199 30.186 49.235 ;
     RECT  37.296 49.037 38.61 49.235 ;
     RECT  32.004 49.199 35.946 49.244 ;
     RECT  21.024 49.235 24.822 49.271 ;
     RECT  30.96 49.199 31.194 49.271 ;
     RECT  19.728 49.199 19.926 49.277 ;
     RECT  21.024 49.271 24.678 49.307 ;
     RECT  14.508 49.199 18.99 49.343 ;
     RECT  19.728 49.277 19.782 49.343 ;
     RECT  21.024 49.307 24.57 49.343 ;
     RECT  32.004 49.244 35.91 49.343 ;
     RECT  39.42 49.199 41.886 49.351 ;
     RECT  21.024 49.343 22.77 49.379 ;
     RECT  24.015 49.343 24.297 49.427 ;
     RECT  32.004 49.343 35.097 49.427 ;
     RECT  37.296 49.235 37.797 49.427 ;
     RECT  42.66 49.199 48.597 49.427 ;
     RECT  2.415 49.235 8.154 49.469 ;
     RECT  9.36 49.199 13.77 49.469 ;
     RECT  14.688 49.343 18.99 49.469 ;
     RECT  19.728 49.343 19.746 49.469 ;
     RECT  21.315 49.379 22.77 49.469 ;
     RECT  26.136 49.235 30.186 49.469 ;
     RECT  32.004 49.427 34.905 49.469 ;
     RECT  38.772 49.351 41.886 49.469 ;
     RECT  42.66 49.427 48.474 49.469 ;
     RECT  26.715 49.469 27.45 49.475 ;
     RECT  2.415 49.469 3.078 49.505 ;
     RECT  3.816 49.469 5.205 49.505 ;
     RECT  6.012 49.469 6.03 49.505 ;
     RECT  7.2 49.469 7.974 49.505 ;
     RECT  11.556 49.469 12.294 49.505 ;
     RECT  13.176 49.469 13.77 49.505 ;
     RECT  21.315 49.469 21.474 49.505 ;
     RECT  22.284 49.469 22.338 49.505 ;
     RECT  33.984 49.469 34.002 49.505 ;
     RECT  37.296 49.427 37.605 49.505 ;
     RECT  41.616 49.469 41.742 49.505 ;
     RECT  42.768 49.469 43.29 49.505 ;
     RECT  44.244 49.469 46.026 49.505 ;
     RECT  46.764 49.469 48.405 49.505 ;
     RECT  10.332 49.469 10.605 49.517 ;
     RECT  18.615 49.469 18.774 49.517 ;
     RECT  17.676 49.469 17.694 49.528 ;
     RECT  30.996 49.271 31.194 49.531 ;
     RECT  32.004 49.469 32.205 49.531 ;
     RECT  7.308 49.505 7.905 49.541 ;
     RECT  22.284 49.505 22.302 49.541 ;
     RECT  40.215 49.469 40.554 49.541 ;
     RECT  41.724 49.505 41.742 49.541 ;
     RECT  44.244 49.505 44.334 49.541 ;
     RECT  45.252 49.505 45.705 49.541 ;
     RECT  46.764 49.505 46.782 49.541 ;
     RECT  32.94 49.469 32.958 49.565 ;
     RECT  4.032 49.505 5.205 49.577 ;
     RECT  9.36 49.469 9.378 49.577 ;
     RECT  11.556 49.505 12.186 49.577 ;
     RECT  13.176 49.505 13.305 49.577 ;
     RECT  14.724 49.469 16.005 49.577 ;
     RECT  29.415 49.469 29.79 49.577 ;
     RECT  30.996 49.531 32.205 49.577 ;
     RECT  44.244 49.541 44.262 49.577 ;
     RECT  45.36 49.541 45.705 49.577 ;
     RECT  47.772 49.505 48.405 49.577 ;
     RECT  42.912 49.505 43.146 49.613 ;
     RECT  45.54 49.577 45.705 49.613 ;
     RECT  4.5 49.577 5.205 49.649 ;
     RECT  14.724 49.577 14.742 49.649 ;
     RECT  42.915 49.613 43.146 49.649 ;
     RECT  2.415 49.505 2.505 49.697 ;
     RECT  5.115 49.649 5.205 49.697 ;
     RECT  7.815 49.541 7.905 49.697 ;
     RECT  10.515 49.517 10.605 49.697 ;
     RECT  13.215 49.577 13.305 49.697 ;
     RECT  15.915 49.577 16.005 49.697 ;
     RECT  18.615 49.517 18.705 49.697 ;
     RECT  21.315 49.505 21.405 49.697 ;
     RECT  24.015 49.427 24.105 49.697 ;
     RECT  26.715 49.475 26.805 49.697 ;
     RECT  29.415 49.577 29.505 49.697 ;
     RECT  32.115 49.577 32.205 49.697 ;
     RECT  34.815 49.469 34.905 49.697 ;
     RECT  37.515 49.505 37.605 49.697 ;
     RECT  40.215 49.541 40.305 49.697 ;
     RECT  42.915 49.649 43.005 49.697 ;
     RECT  45.615 49.613 45.705 49.697 ;
     RECT  48.315 49.577 48.405 49.697 ;
     RECT  11.556 49.577 12.15 51.595 ;
     RECT  11.412 51.595 12.15 51.821 ;
    LAYER M4 ;
     RECT  0.06 43.44 0.097 45.288 ;
     RECT  0.06 19.632 0.133 25.704 ;
     RECT  0.097 43.44 0.569 45.48 ;
     RECT  0.569 43.536 2.329 45.48 ;
     RECT  0.06 13.488 2.401 16.488 ;
     RECT  2.401 2.784 2.408 2.808 ;
     RECT  2.401 12.576 2.408 16.488 ;
     RECT  0.133 19.632 2.408 25.8 ;
     RECT  2.365 30.96 2.408 30.984 ;
     RECT  2.365 38.16 2.408 38.184 ;
     RECT  2.329 43.536 2.408 46.248 ;
     RECT  2.329 47.904 2.408 47.928 ;
     RECT  2.408 2.148 2.512 49.692 ;
     RECT  2.512 2.418 2.704 49.422 ;
     RECT  2.704 32.448 2.801 32.808 ;
     RECT  2.704 34.176 2.945 40.008 ;
     RECT  2.704 12.576 3.017 16.392 ;
     RECT  2.945 34.176 3.059 39.912 ;
     RECT  2.704 9.024 3.443 10.776 ;
     RECT  2.704 43.296 3.443 46.248 ;
     RECT  3.059 34.176 3.449 38.712 ;
     RECT  2.704 5.088 3.557 5.112 ;
     RECT  2.704 30.768 3.557 30.984 ;
     RECT  2.704 47.28 3.557 47.928 ;
     RECT  2.704 2.418 3.661 2.808 ;
     RECT  3.661 2.304 3.701 2.808 ;
     RECT  2.704 6.816 3.701 7.992 ;
     RECT  3.449 34.176 3.701 37.272 ;
     RECT  3.443 10.752 3.829 10.776 ;
     RECT  2.704 26.832 3.841 26.856 ;
     RECT  3.443 9.024 3.884 9.048 ;
     RECT  3.829 10.752 3.913 11.4 ;
     RECT  3.017 12.576 3.913 16.296 ;
     RECT  3.913 10.752 3.917 16.296 ;
     RECT  3.701 34.176 3.953 36.024 ;
     RECT  3.953 34.176 3.997 34.824 ;
     RECT  3.884 8.976 4.025 9.048 ;
     RECT  3.557 30.768 4.028 30.792 ;
     RECT  4.021 29.424 4.069 29.448 ;
     RECT  2.801 32.448 4.069 32.472 ;
     RECT  4.028 30.48 4.115 30.792 ;
     RECT  3.059 39.888 4.165 39.912 ;
     RECT  3.449 38.688 4.309 38.712 ;
     RECT  4.165 39.888 4.309 40.584 ;
     RECT  3.701 7.92 4.345 7.992 ;
     RECT  3.841 26.832 4.453 27.672 ;
     RECT  4.069 28.752 4.453 29.448 ;
     RECT  3.443 43.296 4.489 44.952 ;
     RECT  2.704 19.632 4.497 25.8 ;
     RECT  4.453 26.832 4.497 29.448 ;
     RECT  4.489 43.296 4.525 45.048 ;
     RECT  2.704 17.616 4.693 17.64 ;
     RECT  3.701 37.248 4.777 37.272 ;
     RECT  4.525 42.912 4.777 45.048 ;
     RECT  4.633 49.152 4.844 49.176 ;
     RECT  3.701 6.816 4.885 6.84 ;
     RECT  4.069 32.448 4.885 33.096 ;
     RECT  4.885 32.304 4.981 33.096 ;
     RECT  3.997 34.176 4.981 34.344 ;
     RECT  3.443 46.176 5.065 46.248 ;
     RECT  3.557 47.28 5.065 47.304 ;
     RECT  4.309 38.688 5.101 40.584 ;
     RECT  3.701 2.304 5.108 2.328 ;
     RECT  4.885 5.856 5.108 6.84 ;
     RECT  4.345 7.92 5.108 8.568 ;
     RECT  3.917 12.336 5.108 16.296 ;
     RECT  4.693 17.616 5.108 18.408 ;
     RECT  4.497 19.632 5.108 29.448 ;
     RECT  4.115 30.576 5.108 30.792 ;
     RECT  4.981 32.304 5.108 34.344 ;
     RECT  4.777 37.248 5.108 37.464 ;
     RECT  5.101 38.688 5.108 40.872 ;
     RECT  4.777 42.48 5.108 45.048 ;
     RECT  5.065 46.176 5.108 47.304 ;
     RECT  4.844 48.384 5.108 49.176 ;
     RECT  5.108 2.148 5.212 49.692 ;
     RECT  5.212 2.304 5.404 49.422 ;
     RECT  5.404 30.576 5.465 34.44 ;
     RECT  5.404 42 5.501 47.88 ;
     RECT  5.404 27.648 5.537 27.72 ;
     RECT  5.404 2.304 5.753 2.328 ;
     RECT  5.404 28.752 6.113 29.064 ;
     RECT  5.404 17.04 6.177 26.664 ;
     RECT  5.465 31.296 6.257 34.44 ;
     RECT  6.177 18.192 6.293 26.664 ;
     RECT  6.257 31.296 6.323 34.056 ;
     RECT  5.404 36.336 6.397 37.464 ;
     RECT  5.404 38.544 6.397 39.624 ;
     RECT  5.537 27.648 6.401 27.672 ;
     RECT  5.501 43.296 6.419 47.88 ;
     RECT  6.323 31.296 6.437 31.416 ;
     RECT  5.404 40.848 6.437 40.872 ;
     RECT  5.404 48.912 6.445 49.08 ;
     RECT  5.404 3.696 6.508 6.168 ;
     RECT  5.501 42 6.541 42.264 ;
     RECT  6.419 43.296 6.541 45.576 ;
     RECT  5.404 11.76 6.545 15.816 ;
     RECT  5.404 7.248 6.613 8.568 ;
     RECT  5.404 9.648 6.613 9.768 ;
     RECT  6.397 36.336 6.689 39.624 ;
     RECT  6.613 7.248 6.721 9.768 ;
     RECT  6.419 46.848 6.725 47.88 ;
     RECT  6.445 48.912 6.725 49.032 ;
     RECT  6.508 3.696 6.757 4.536 ;
     RECT  6.541 42 6.761 45.576 ;
     RECT  6.761 42 6.805 45.528 ;
     RECT  6.177 17.04 6.829 17.112 ;
     RECT  6.805 41.136 6.833 45.528 ;
     RECT  6.829 16.896 7.261 17.112 ;
     RECT  6.293 18.192 7.261 25.8 ;
     RECT  6.113 28.752 7.333 28.776 ;
     RECT  6.508 5.856 7.34 6.168 ;
     RECT  6.721 7.248 7.34 10.056 ;
     RECT  6.323 32.832 7.381 34.056 ;
     RECT  7.333 28.176 7.621 28.776 ;
     RECT  6.901 30.144 7.621 30.168 ;
     RECT  6.757 3.36 7.669 4.536 ;
     RECT  6.545 11.952 7.693 15.816 ;
     RECT  7.261 16.896 7.693 25.8 ;
     RECT  6.725 47.424 7.729 47.88 ;
     RECT  6.725 48.912 7.729 48.936 ;
     RECT  7.669 3.36 7.808 4.68 ;
     RECT  7.34 5.856 7.808 10.056 ;
     RECT  7.693 11.952 7.808 25.8 ;
     RECT  7.292 26.976 7.808 27 ;
     RECT  7.621 28.176 7.808 30.168 ;
     RECT  6.437 31.296 7.808 31.32 ;
     RECT  7.381 32.304 7.808 34.056 ;
     RECT  6.901 35.808 7.808 35.832 ;
     RECT  6.689 36.912 7.808 39.624 ;
     RECT  6.833 41.136 7.808 45.144 ;
     RECT  7.729 47.424 7.808 48.936 ;
     RECT  7.808 2.148 7.912 49.692 ;
     RECT  7.912 2.256 8.104 49.422 ;
     RECT  8.104 3.36 8.165 4.536 ;
     RECT  8.165 3.36 8.243 3.432 ;
     RECT  8.104 36.912 8.243 45.48 ;
     RECT  8.104 12.192 8.309 26.712 ;
     RECT  8.104 7.296 8.381 8.568 ;
     RECT  8.243 36.912 8.417 37.608 ;
     RECT  8.104 48.432 8.417 48.984 ;
     RECT  8.243 38.64 8.489 45.48 ;
     RECT  8.417 36.912 8.579 36.936 ;
     RECT  8.104 28.752 8.633 34.68 ;
     RECT  8.104 2.256 8.741 2.28 ;
     RECT  8.381 7.296 8.741 7.32 ;
     RECT  8.489 41.424 8.915 45.48 ;
     RECT  8.165 4.512 8.956 4.536 ;
     RECT  8.309 16.896 8.957 26.712 ;
     RECT  8.957 22.848 9.133 26.712 ;
     RECT  8.104 47.28 9.173 47.352 ;
     RECT  8.633 31.68 9.241 34.68 ;
     RECT  8.104 5.856 9.245 5.88 ;
     RECT  8.309 12.192 9.277 13.656 ;
     RECT  8.309 14.88 9.277 15.864 ;
     RECT  8.915 43.872 9.277 45.48 ;
     RECT  9.277 12.192 9.421 15.864 ;
     RECT  8.957 16.896 9.421 21.816 ;
     RECT  8.381 8.544 9.529 8.568 ;
     RECT  8.104 9.936 9.637 10.824 ;
     RECT  8.633 28.752 9.637 30.408 ;
     RECT  8.489 38.64 9.637 40.008 ;
     RECT  8.915 41.424 9.637 42.072 ;
     RECT  9.241 31.68 9.709 34.776 ;
     RECT  8.417 48.96 9.709 48.984 ;
     RECT  9.637 9.936 9.74 11.208 ;
     RECT  9.421 12.192 9.74 21.816 ;
     RECT  9.637 27.984 9.781 30.408 ;
     RECT  9.709 31.68 9.781 35.352 ;
     RECT  9.781 27.984 9.817 35.352 ;
     RECT  9.133 22.848 9.925 26.856 ;
     RECT  9.817 27.888 9.925 35.352 ;
     RECT  8.243 3.36 9.932 3.384 ;
     RECT  9.853 5.232 9.932 5.256 ;
     RECT  9.529 7.968 9.973 8.568 ;
     RECT  9.973 7.584 10.033 8.568 ;
     RECT  9.74 9.936 10.033 21.816 ;
     RECT  9.925 22.848 10.033 35.352 ;
     RECT  9.277 43.872 10.033 46.104 ;
     RECT  10.033 7.584 10.069 21.816 ;
     RECT  10.033 22.848 10.069 35.976 ;
     RECT  9.637 38.16 10.261 42.072 ;
     RECT  9.709 48.912 10.261 48.984 ;
     RECT  9.173 47.328 10.285 47.352 ;
     RECT  10.261 48.48 10.285 48.984 ;
     RECT  10.033 43.872 10.309 46.344 ;
     RECT  10.285 47.328 10.321 48.984 ;
     RECT  10.309 43.632 10.357 46.344 ;
     RECT  10.321 47.328 10.357 49.512 ;
     RECT  9.932 2.88 10.508 3.384 ;
     RECT  9.932 4.512 10.508 5.256 ;
     RECT  10.069 7.584 10.508 35.976 ;
     RECT  10.261 37.968 10.508 42.072 ;
     RECT  10.357 43.632 10.508 49.512 ;
     RECT  10.508 2.148 10.612 49.692 ;
     RECT  10.612 2.418 10.804 49.512 ;
     RECT  10.804 30.144 10.865 30.456 ;
     RECT  10.804 43.872 10.865 49.512 ;
     RECT  10.804 40.848 10.901 41.448 ;
     RECT  10.865 48.144 10.931 49.512 ;
     RECT  10.804 31.632 10.945 36.024 ;
     RECT  10.804 3.072 11.009 4.152 ;
     RECT  10.865 43.872 11.027 47.064 ;
     RECT  10.931 48.144 11.171 48.648 ;
     RECT  11.027 43.92 11.189 47.064 ;
     RECT  11.189 46.752 11.212 47.064 ;
     RECT  10.804 6.576 11.297 7.992 ;
     RECT  11.009 4.128 11.333 4.152 ;
     RECT  11.189 43.92 11.333 45.72 ;
     RECT  10.945 31.68 11.369 36.024 ;
     RECT  11.369 31.68 11.459 31.704 ;
     RECT  11.401 51.6 11.555 51.768 ;
     RECT  11.009 3.072 11.585 3.096 ;
     RECT  10.804 18.144 11.692 29.064 ;
     RECT  11.555 51.744 11.699 51.768 ;
     RECT  11.369 32.736 11.801 36.024 ;
     RECT  10.804 11.184 11.941 17.16 ;
     RECT  11.692 22.512 11.941 29.064 ;
     RECT  10.865 30.144 11.941 30.168 ;
     RECT  10.804 42.672 11.941 42.696 ;
     RECT  11.801 32.736 12.009 35.352 ;
     RECT  11.941 10.848 12.013 17.16 ;
     RECT  11.692 18.144 12.013 21.384 ;
     RECT  11.297 6.672 12.049 7.992 ;
     RECT  11.941 22.512 12.085 30.168 ;
     RECT  11.941 31.248 12.085 31.272 ;
     RECT  12.013 36.96 12.085 36.984 ;
     RECT  11.333 43.92 12.085 45.624 ;
     RECT  12.049 6.672 12.089 8.568 ;
     RECT  10.804 39.312 12.125 39.768 ;
     RECT  12.125 39.6 12.157 39.768 ;
     RECT  10.901 40.848 12.157 40.872 ;
     RECT  12.009 33.888 12.227 35.352 ;
     RECT  12.085 36.96 12.229 37.608 ;
     RECT  12.089 8.544 12.332 8.568 ;
     RECT  10.804 9.744 12.332 9.816 ;
     RECT  11.212 46.8 12.409 47.064 ;
     RECT  11.171 48.144 12.409 48.456 ;
     RECT  12.409 46.8 12.625 48.504 ;
     RECT  12.085 43.824 12.733 45.624 ;
     RECT  12.625 46.608 12.733 48.504 ;
     RECT  12.157 39.6 12.757 40.872 ;
     RECT  11.941 42.192 12.757 42.696 ;
     RECT  12.013 10.848 12.949 21.384 ;
     RECT  12.085 22.512 12.949 31.272 ;
     RECT  12.757 39.6 13.093 42.696 ;
     RECT  12.332 2.256 13.208 2.28 ;
     RECT  12.089 6.672 13.208 7.368 ;
     RECT  12.332 8.544 13.208 9.816 ;
     RECT  12.949 10.848 13.208 31.272 ;
     RECT  12.009 32.736 13.208 32.76 ;
     RECT  12.227 34.368 13.208 35.352 ;
     RECT  12.229 36.96 13.208 37.896 ;
     RECT  13.093 38.976 13.208 42.696 ;
     RECT  12.733 43.824 13.208 48.504 ;
     RECT  13.208 2.148 13.312 49.692 ;
     RECT  13.312 2.418 13.504 49.422 ;
     RECT  13.504 11.76 13.565 22.824 ;
     RECT  13.565 18.048 13.619 22.824 ;
     RECT  13.504 39.312 13.619 47.928 ;
     RECT  13.504 24 13.709 34.824 ;
     RECT  13.619 39.312 13.709 42.168 ;
     RECT  13.619 19.776 13.745 22.824 ;
     RECT  13.709 33.552 13.745 34.824 ;
     RECT  13.745 20.88 13.889 22.824 ;
     RECT  13.745 19.776 13.925 19.8 ;
     RECT  13.565 11.76 14.177 16.92 ;
     RECT  13.504 3.936 14.285 3.96 ;
     RECT  13.745 33.552 14.465 33.576 ;
     RECT  13.504 49.296 14.537 49.32 ;
     RECT  13.709 39.696 14.605 42.168 ;
     RECT  13.619 43.248 14.605 47.928 ;
     RECT  13.745 34.704 14.713 34.824 ;
     RECT  14.605 39.696 14.713 47.928 ;
     RECT  13.504 36.864 14.773 37.944 ;
     RECT  13.889 20.88 14.785 21.384 ;
     RECT  14.773 36.864 14.789 38.664 ;
     RECT  13.889 22.512 14.821 22.824 ;
     RECT  13.709 24 14.821 31.8 ;
     RECT  14.789 37.584 14.825 38.664 ;
     RECT  13.504 8.4 14.861 10.104 ;
     RECT  14.177 14.448 14.893 16.92 ;
     RECT  13.619 18.048 14.893 18.744 ;
     RECT  14.893 14.448 14.897 18.744 ;
     RECT  14.785 20.304 15.073 21.384 ;
     RECT  14.821 22.512 15.073 31.8 ;
     RECT  15.073 20.304 15.109 31.8 ;
     RECT  15.109 20.304 15.145 32.04 ;
     RECT  14.897 15.552 15.212 18.744 ;
     RECT  15.145 20.064 15.212 32.04 ;
     RECT  14.825 37.632 15.217 38.664 ;
     RECT  14.713 39.696 15.217 49.032 ;
     RECT  13.504 6.528 15.505 7.368 ;
     RECT  14.861 8.4 15.505 9.816 ;
     RECT  15.397 4.848 15.637 4.872 ;
     RECT  15.505 6.528 15.637 9.816 ;
     RECT  14.177 11.76 15.721 13.08 ;
     RECT  15.541 33.024 15.721 33.048 ;
     RECT  14.713 34.224 15.721 34.824 ;
     RECT  15.637 4.848 15.793 9.816 ;
     RECT  15.721 11.232 15.865 13.08 ;
     RECT  15.637 2.592 15.908 2.616 ;
     RECT  15.793 3.936 15.908 9.816 ;
     RECT  15.865 10.896 15.908 13.08 ;
     RECT  14.897 14.448 15.908 14.472 ;
     RECT  15.212 15.552 15.908 32.04 ;
     RECT  15.721 33.024 15.908 34.824 ;
     RECT  15.325 36.336 15.908 36.36 ;
     RECT  15.217 37.632 15.908 49.032 ;
     RECT  15.908 2.148 16.012 49.692 ;
     RECT  16.012 2.418 16.204 49.422 ;
     RECT  16.204 2.592 16.444 33.576 ;
     RECT  16.204 39.264 16.589 49.224 ;
     RECT  16.444 2.592 16.656 30.36 ;
     RECT  16.656 10.8 16.733 30.36 ;
     RECT  16.589 39.264 16.805 39.864 ;
     RECT  16.204 34.752 17.123 37.944 ;
     RECT  16.656 2.592 17.136 9.672 ;
     RECT  16.444 31.536 17.201 33.576 ;
     RECT  17.136 2.688 17.309 9.672 ;
     RECT  17.309 2.688 17.345 7.224 ;
     RECT  17.345 2.688 17.381 5.784 ;
     RECT  17.201 32.448 17.381 33.576 ;
     RECT  17.345 6.768 17.489 7.224 ;
     RECT  16.805 39.312 17.561 39.864 ;
     RECT  17.123 36.096 17.597 37.944 ;
     RECT  17.381 5.232 17.633 5.784 ;
     RECT  16.589 41.184 17.665 49.224 ;
     RECT  17.597 37.44 17.881 37.944 ;
     RECT  17.561 39.312 17.881 39.816 ;
     RECT  16.733 10.8 18.169 30.168 ;
     RECT  17.123 34.752 18.469 34.776 ;
     RECT  17.597 36.096 18.469 36.36 ;
     RECT  17.881 37.44 18.565 39.816 ;
     RECT  17.665 41.184 18.565 49.512 ;
     RECT  17.381 2.688 18.608 3.528 ;
     RECT  17.633 5.52 18.608 5.784 ;
     RECT  17.489 7.2 18.608 7.224 ;
     RECT  17.309 9.024 18.608 9.672 ;
     RECT  18.169 10.8 18.608 30.888 ;
     RECT  17.381 32.448 18.608 32.472 ;
     RECT  18.469 33.552 18.608 33.576 ;
     RECT  18.469 34.752 18.608 36.36 ;
     RECT  18.565 37.44 18.608 49.512 ;
     RECT  18.608 2.148 18.712 49.692 ;
     RECT  18.712 2.256 18.785 49.512 ;
     RECT  18.785 2.256 18.904 49.422 ;
     RECT  18.904 10.992 19.043 28.44 ;
     RECT  19.043 22.224 19.109 28.44 ;
     RECT  19.043 10.992 19.228 21.24 ;
     RECT  18.904 43.584 19.283 46.92 ;
     RECT  19.228 10.992 19.289 16.92 ;
     RECT  18.904 36.336 19.397 37.896 ;
     RECT  18.904 39.504 19.505 40.584 ;
     RECT  19.397 36.336 19.613 36.408 ;
     RECT  19.505 40.56 19.613 40.584 ;
     RECT  19.397 37.44 19.721 37.896 ;
     RECT  18.904 2.256 19.897 6.648 ;
     RECT  18.904 7.68 19.897 9.576 ;
     RECT  18.904 29.616 19.897 31.176 ;
     RECT  18.904 48.768 19.937 49.272 ;
     RECT  19.897 2.256 19.973 9.576 ;
     RECT  19.973 2.352 20.009 9.576 ;
     RECT  19.897 29.616 20.113 31.464 ;
     RECT  20.113 29.616 20.117 31.896 ;
     RECT  18.904 42.144 20.149 42.168 ;
     RECT  20.117 30.096 20.185 31.896 ;
     RECT  19.937 48.768 20.185 48.936 ;
     RECT  19.969 35.328 20.221 35.352 ;
     RECT  19.289 10.992 20.329 13.896 ;
     RECT  19.289 14.928 20.329 16.92 ;
     RECT  20.149 42.144 20.329 42.744 ;
     RECT  19.283 43.872 20.329 46.92 ;
     RECT  20.185 48.24 20.329 48.936 ;
     RECT  19.721 37.536 20.401 37.896 ;
     RECT  20.009 7.68 20.437 9.576 ;
     RECT  20.185 30.096 20.509 32.568 ;
     RECT  20.293 34.128 20.509 34.152 ;
     RECT  20.221 35.28 20.509 35.352 ;
     RECT  20.329 10.992 20.581 16.92 ;
     RECT  19.228 18 20.581 21.24 ;
     RECT  20.329 42.144 20.581 46.92 ;
     RECT  20.329 47.904 20.581 48.936 ;
     RECT  20.401 37.536 20.725 38.424 ;
     RECT  19.505 39.504 20.725 39.528 ;
     RECT  20.581 10.992 20.941 21.24 ;
     RECT  19.109 22.32 20.941 28.44 ;
     RECT  20.509 30.096 21.013 35.352 ;
     RECT  19.613 36.336 21.013 36.36 ;
     RECT  20.581 42.144 21.061 48.936 ;
     RECT  20.437 7.68 21.157 9.912 ;
     RECT  21.061 42.144 21.157 49.032 ;
     RECT  21.013 30.096 21.193 36.36 ;
     RECT  20.725 37.536 21.265 39.528 ;
     RECT  21.157 40.704 21.265 49.032 ;
     RECT  20.009 2.352 21.301 6.6 ;
     RECT  21.157 7.632 21.301 9.912 ;
     RECT  21.301 2.352 21.308 9.912 ;
     RECT  20.941 10.992 21.308 28.44 ;
     RECT  21.193 29.856 21.308 36.36 ;
     RECT  21.265 37.536 21.308 49.032 ;
     RECT  21.308 2.148 21.412 49.692 ;
     RECT  21.412 2.418 21.604 49.422 ;
     RECT  21.604 34.464 21.665 35.304 ;
     RECT  21.604 18.528 21.731 32.808 ;
     RECT  21.604 40.416 21.809 41.256 ;
     RECT  21.731 19.776 22.061 32.808 ;
     RECT  21.604 2.496 22.259 16.296 ;
     RECT  21.604 43.152 22.259 49.032 ;
     RECT  22.259 2.496 22.313 7.464 ;
     RECT  22.313 2.496 22.349 6.84 ;
     RECT  22.061 19.776 22.349 29.112 ;
     RECT  22.349 6.72 22.385 6.84 ;
     RECT  22.061 30.096 22.385 32.808 ;
     RECT  22.349 29.088 22.493 29.112 ;
     RECT  22.349 19.776 22.529 27.96 ;
     RECT  21.731 18.528 22.633 18.648 ;
     RECT  21.809 40.416 22.7 41.208 ;
     RECT  22.259 8.448 22.705 16.296 ;
     RECT  22.7 39.888 22.787 41.208 ;
     RECT  22.529 19.776 22.817 27.912 ;
     RECT  22.349 2.496 22.853 5.496 ;
     RECT  22.787 40.416 22.853 41.208 ;
     RECT  22.817 19.872 22.889 27.912 ;
     RECT  22.259 43.68 22.925 49.032 ;
     RECT  21.604 37.872 22.993 38.424 ;
     RECT  21.665 35.28 23.125 35.304 ;
     RECT  22.385 30.096 23.317 31.224 ;
     RECT  22.633 17.904 23.389 18.648 ;
     RECT  23.317 29.856 23.413 31.224 ;
     RECT  22.385 32.208 23.413 32.808 ;
     RECT  22.853 40.8 23.461 41.208 ;
     RECT  22.853 4.08 23.557 5.496 ;
     RECT  22.385 6.816 23.557 6.84 ;
     RECT  23.413 29.856 23.605 32.808 ;
     RECT  23.605 29.856 23.677 33.384 ;
     RECT  23.461 42.576 23.701 42.6 ;
     RECT  22.925 43.68 23.701 47.448 ;
     RECT  23.389 17.904 23.713 18.792 ;
     RECT  22.705 8.448 23.716 16.92 ;
     RECT  23.713 17.904 23.716 18.84 ;
     RECT  23.125 35.28 23.857 35.4 ;
     RECT  22.853 2.496 24.008 2.856 ;
     RECT  23.557 4.08 24.008 6.936 ;
     RECT  23.716 8.448 24.008 18.84 ;
     RECT  22.889 20.16 24.008 27.912 ;
     RECT  23.677 29.376 24.008 33.384 ;
     RECT  23.857 34.896 24.008 35.4 ;
     RECT  23.857 36.624 24.008 36.648 ;
     RECT  22.993 37.872 24.008 38.76 ;
     RECT  23.461 40.8 24.008 41.496 ;
     RECT  23.701 42.576 24.008 47.448 ;
     RECT  22.925 49.008 24.008 49.032 ;
     RECT  24.008 2.148 24.112 49.692 ;
     RECT  24.112 2.418 24.304 49.422 ;
     RECT  24.304 8.448 24.419 8.808 ;
     RECT  24.304 10.08 24.437 16.008 ;
     RECT  24.437 10.08 24.509 15.672 ;
     RECT  24.304 2.784 24.545 5.064 ;
     RECT  24.304 46.224 24.545 47.448 ;
     RECT  24.304 18.768 24.581 32.616 ;
     RECT  24.304 41.472 24.581 41.496 ;
     RECT  24.304 43.344 24.581 45.048 ;
     RECT  24.304 6.816 24.689 6.936 ;
     RECT  24.304 17.136 24.797 17.16 ;
     RECT  24.509 10.896 24.899 15.672 ;
     RECT  24.581 22.032 24.977 32.616 ;
     RECT  24.304 36.624 25.049 39.528 ;
     RECT  24.304 33.6 25.091 33.624 ;
     RECT  24.304 34.896 25.091 34.92 ;
     RECT  24.545 2.832 25.121 5.064 ;
     RECT  24.419 8.448 25.405 8.472 ;
     RECT  25.049 37.152 25.405 39.528 ;
     RECT  25.405 8.256 25.441 8.472 ;
     RECT  24.689 6.816 25.513 6.84 ;
     RECT  24.977 22.032 25.612 28.824 ;
     RECT  24.581 43.344 25.621 44.952 ;
     RECT  24.545 46.224 25.621 46.824 ;
     RECT  25.441 8.16 25.625 8.472 ;
     RECT  25.612 27.792 25.625 28.824 ;
     RECT  24.304 48.768 25.657 48.792 ;
     RECT  25.405 37.152 25.667 40.104 ;
     RECT  25.121 2.976 25.697 5.064 ;
     RECT  25.621 43.104 25.697 44.952 ;
     RECT  24.977 29.856 25.733 32.616 ;
     RECT  25.513 10.272 25.981 10.296 ;
     RECT  25.625 8.256 26.125 8.472 ;
     RECT  25.621 46.08 26.125 46.824 ;
     RECT  25.657 48.672 26.125 48.792 ;
     RECT  25.981 10.272 26.161 10.392 ;
     RECT  24.899 11.664 26.161 15.672 ;
     RECT  24.581 18.768 26.305 20.856 ;
     RECT  25.612 22.032 26.305 26.616 ;
     RECT  26.125 48.672 26.413 48.984 ;
     RECT  26.06 33.6 26.449 33.624 ;
     RECT  26.053 34.944 26.449 34.968 ;
     RECT  26.125 8.256 26.485 9 ;
     RECT  26.161 10.272 26.485 15.672 ;
     RECT  26.125 46.08 26.557 47.16 ;
     RECT  26.449 33.6 26.629 34.968 ;
     RECT  25.625 27.984 26.701 28.824 ;
     RECT  25.733 29.856 26.701 31.8 ;
     RECT  25.697 3.312 26.708 5.064 ;
     RECT  25.513 6.384 26.708 6.84 ;
     RECT  26.485 8.256 26.708 15.672 ;
     RECT  25.801 17.616 26.708 17.64 ;
     RECT  26.305 18.768 26.708 26.616 ;
     RECT  26.701 27.984 26.708 31.8 ;
     RECT  26.629 33.024 26.708 34.968 ;
     RECT  25.667 37.152 26.708 37.176 ;
     RECT  25.667 38.208 26.708 40.104 ;
     RECT  25.801 41.904 26.708 41.928 ;
     RECT  25.697 43.104 26.708 43.56 ;
     RECT  25.697 44.928 26.708 44.952 ;
     RECT  26.557 45.984 26.708 47.16 ;
     RECT  26.413 48.432 26.708 48.984 ;
     RECT  26.708 2.148 26.812 49.692 ;
     RECT  26.812 2.418 27.004 49.464 ;
     RECT  27.004 40.8 27.155 43.56 ;
     RECT  27.155 40.8 27.196 43.368 ;
     RECT  27.004 34.368 27.389 34.968 ;
     RECT  27.004 18.192 27.395 30.168 ;
     RECT  27.004 33.024 27.461 33.048 ;
     RECT  27.004 31.392 27.539 31.8 ;
     RECT  27.004 2.64 27.628 6.84 ;
     RECT  27.395 18.192 27.677 20.712 ;
     RECT  27.196 41.376 27.713 43.368 ;
     RECT  27.628 4.368 27.731 6.84 ;
     RECT  27.731 4.368 27.965 5.304 ;
     RECT  27.731 6.384 27.965 6.84 ;
     RECT  27.004 16.656 28.001 16.68 ;
     RECT  27.004 36.432 28.001 39.672 ;
     RECT  27.004 8.448 28.069 8.952 ;
     RECT  27.004 10.368 28.069 15.48 ;
     RECT  27.965 6.384 28.073 6.6 ;
     RECT  28.073 6.384 28.109 6.408 ;
     RECT  28.001 36.432 28.165 37.416 ;
     RECT  27.713 43.104 28.177 43.368 ;
     RECT  28.001 38.4 28.213 39.672 ;
     RECT  27.713 41.376 28.213 41.928 ;
     RECT  28.069 8.448 28.249 15.48 ;
     RECT  28.213 38.4 28.259 41.928 ;
     RECT  27.539 31.68 28.285 31.8 ;
     RECT  27.395 21.696 28.289 30.168 ;
     RECT  28.165 36.24 28.297 37.416 ;
     RECT  27.965 4.368 28.325 4.68 ;
     RECT  27.628 2.736 28.361 3.336 ;
     RECT  28.289 21.696 28.361 29.112 ;
     RECT  27.677 18.768 28.645 20.712 ;
     RECT  28.645 18.72 28.689 20.712 ;
     RECT  28.361 21.696 28.689 29.016 ;
     RECT  28.289 30.096 28.789 30.168 ;
     RECT  28.259 39.456 28.789 41.928 ;
     RECT  28.177 43.104 28.789 43.752 ;
     RECT  28.789 30.096 28.933 30.648 ;
     RECT  28.285 31.68 28.933 31.992 ;
     RECT  27.389 34.368 28.969 34.68 ;
     RECT  28.249 7.968 28.988 15.48 ;
     RECT  28.933 30.096 29.041 31.992 ;
     RECT  29.041 30.096 29.077 32.04 ;
     RECT  29.077 30.096 29.149 32.28 ;
     RECT  28.988 7.968 29.269 16.296 ;
     RECT  28.325 4.416 29.365 4.68 ;
     RECT  28.361 2.736 29.408 2.904 ;
     RECT  29.365 4.416 29.408 5.208 ;
     RECT  29.269 7.392 29.408 16.296 ;
     RECT  28.689 18.72 29.408 29.016 ;
     RECT  29.149 30.096 29.408 32.52 ;
     RECT  28.969 34.368 29.408 34.776 ;
     RECT  28.297 36.24 29.408 36.264 ;
     RECT  28.297 37.248 29.408 37.416 ;
     RECT  28.259 38.4 29.408 38.424 ;
     RECT  28.789 39.456 29.408 43.752 ;
     RECT  27.004 44.928 29.408 49.464 ;
     RECT  29.408 2.148 29.512 49.692 ;
     RECT  29.512 2.256 29.549 49.464 ;
     RECT  29.549 2.256 29.704 49.422 ;
     RECT  29.704 7.968 29.873 15.528 ;
     RECT  29.704 30.24 30.089 32.52 ;
     RECT  29.704 34.368 30.197 38.184 ;
     RECT  29.704 28.416 30.233 28.824 ;
     RECT  30.197 34.368 30.233 37.224 ;
     RECT  29.704 4.128 30.413 6.696 ;
     RECT  30.233 34.368 30.521 35.352 ;
     RECT  30.089 30.24 30.593 31.944 ;
     RECT  29.704 16.512 30.755 20.424 ;
     RECT  29.704 21.504 30.769 27.288 ;
     RECT  29.704 45.936 30.769 48.936 ;
     RECT  30.755 18.768 30.805 20.424 ;
     RECT  30.769 21.504 30.805 27.384 ;
     RECT  30.593 30.24 30.805 30.744 ;
     RECT  30.593 31.92 30.809 31.944 ;
     RECT  30.521 34.368 30.809 34.968 ;
     RECT  30.233 37.2 30.809 37.224 ;
     RECT  30.809 34.368 30.845 34.68 ;
     RECT  30.805 18.768 30.851 27.384 ;
     RECT  29.873 8.448 30.881 15.528 ;
     RECT  30.851 18.768 30.889 23.352 ;
     RECT  30.805 30 30.889 30.744 ;
     RECT  30.413 4.224 30.953 6.696 ;
     RECT  30.881 9.6 30.985 15.528 ;
     RECT  30.755 16.512 30.985 17.64 ;
     RECT  29.704 40.56 30.985 44.952 ;
     RECT  30.769 45.936 30.985 48.984 ;
     RECT  30.851 24.384 30.989 27.384 ;
     RECT  30.985 40.56 31.021 48.984 ;
     RECT  30.985 9.6 31.091 17.64 ;
     RECT  30.989 24.624 31.093 27.384 ;
     RECT  31.093 24.624 31.201 27.432 ;
     RECT  30.233 28.416 31.201 28.728 ;
     RECT  31.201 24.624 31.417 28.728 ;
     RECT  30.845 34.368 31.597 34.392 ;
     RECT  31.021 40.56 31.597 49.032 ;
     RECT  31.417 24.624 31.777 28.968 ;
     RECT  30.881 8.448 31.849 8.52 ;
     RECT  30.889 18.768 31.849 23.304 ;
     RECT  31.849 7.776 31.949 8.52 ;
     RECT  31.091 9.6 31.949 15.336 ;
     RECT  30.953 4.656 31.957 6.696 ;
     RECT  31.949 7.776 31.957 15.336 ;
     RECT  31.597 34.176 31.957 34.392 ;
     RECT  31.532 35.664 31.957 35.688 ;
     RECT  31.957 4.656 31.993 15.336 ;
     RECT  31.309 37.008 31.993 37.032 ;
     RECT  31.091 16.56 32.101 17.64 ;
     RECT  31.849 18.672 32.101 23.304 ;
     RECT  29.704 2.256 32.108 2.904 ;
     RECT  31.993 4.512 32.108 15.336 ;
     RECT  32.101 16.56 32.108 23.304 ;
     RECT  31.777 24.624 32.108 29.016 ;
     RECT  30.889 30.24 32.108 30.744 ;
     RECT  31.957 33.36 32.108 35.688 ;
     RECT  31.993 37.008 32.108 37.944 ;
     RECT  31.849 39.216 32.108 39.24 ;
     RECT  31.597 40.56 32.108 49.56 ;
     RECT  32.108 2.148 32.212 49.692 ;
     RECT  32.212 2.418 32.404 49.56 ;
     RECT  32.404 16.56 32.537 27.096 ;
     RECT  32.404 34.176 32.537 34.968 ;
     RECT  32.404 10.128 32.573 15.336 ;
     RECT  32.404 28.416 32.675 30.744 ;
     RECT  32.404 3.312 32.753 8.52 ;
     RECT  32.753 3.312 32.933 8.232 ;
     RECT  32.404 37.632 32.941 41.16 ;
     RECT  32.404 46.224 32.969 49.56 ;
     RECT  32.573 11.424 33.005 15.336 ;
     RECT  32.537 16.56 33.005 26.328 ;
     RECT  32.537 34.368 33.059 34.968 ;
     RECT  32.941 37.632 33.059 38.76 ;
     RECT  32.404 36.432 33.077 36.456 ;
     RECT  33.059 38.112 33.155 38.76 ;
     RECT  32.941 39.792 33.155 41.16 ;
     RECT  32.933 4.992 33.401 8.232 ;
     RECT  32.404 42.48 33.505 44.952 ;
     RECT  32.969 46.224 33.505 49.464 ;
     RECT  33.155 40.848 33.577 41.16 ;
     RECT  33.505 42.48 33.577 45.048 ;
     RECT  33.577 40.848 33.581 45.048 ;
     RECT  33.505 46.08 33.725 49.464 ;
     RECT  33.059 34.944 33.757 34.968 ;
     RECT  32.675 30.096 33.781 30.744 ;
     RECT  32.404 32.352 33.781 33.096 ;
     RECT  32.933 3.312 33.829 3.96 ;
     RECT  33.781 30.096 33.937 33.096 ;
     RECT  32.675 28.416 34.045 29.112 ;
     RECT  33.937 30.096 34.045 33.672 ;
     RECT  33.005 17.232 34.117 26.328 ;
     RECT  33.401 6.864 34.225 8.232 ;
     RECT  33.155 39.792 34.261 39.816 ;
     RECT  33.581 40.848 34.261 41.592 ;
     RECT  33.005 11.664 34.297 14.808 ;
     RECT  32.573 10.128 34.369 10.152 ;
     RECT  33.155 38.16 34.453 38.76 ;
     RECT  33.581 43.104 34.477 45.048 ;
     RECT  33.725 46.08 34.477 46.632 ;
     RECT  34.369 10.128 34.585 10.488 ;
     RECT  33.829 2.784 34.765 3.96 ;
     RECT  33.401 4.992 34.765 5.688 ;
     RECT  34.225 6.864 34.765 8.952 ;
     RECT  34.117 16.512 34.801 26.328 ;
     RECT  34.765 2.784 34.808 5.688 ;
     RECT  34.765 6.816 34.808 8.952 ;
     RECT  34.585 10.128 34.808 10.68 ;
     RECT  34.297 11.664 34.808 15.048 ;
     RECT  34.801 16.368 34.808 26.328 ;
     RECT  34.045 28.416 34.808 33.672 ;
     RECT  33.757 34.944 34.808 35.88 ;
     RECT  34.453 37.44 34.808 38.76 ;
     RECT  34.261 39.792 34.808 41.592 ;
     RECT  34.477 43.104 34.808 46.632 ;
     RECT  33.725 47.712 34.808 49.464 ;
     RECT  34.808 2.148 34.912 49.692 ;
     RECT  34.912 2.418 35.104 49.422 ;
     RECT  35.104 10.128 35.129 15.048 ;
     RECT  35.104 42.96 35.165 49.032 ;
     RECT  35.104 31.92 35.219 36.36 ;
     RECT  35.219 31.92 35.245 34.824 ;
     RECT  35.104 16.368 35.309 30.36 ;
     RECT  35.104 6.816 35.345 7.752 ;
     RECT  35.165 44.88 35.417 49.032 ;
     RECT  35.129 12.336 35.489 15.048 ;
     RECT  35.104 38.16 35.741 38.904 ;
     RECT  35.309 21.648 35.813 30.36 ;
     RECT  35.245 31.92 35.813 32.28 ;
     RECT  35.813 30.336 36.029 30.36 ;
     RECT  35.417 45.984 36.029 49.032 ;
     RECT  35.309 16.368 36.065 20.568 ;
     RECT  35.245 33.408 36.065 34.824 ;
     RECT  36.065 33.648 36.137 34.824 ;
     RECT  35.741 38.16 36.137 38.76 ;
     RECT  35.129 10.128 36.188 10.728 ;
     RECT  36.188 10.128 36.275 11.064 ;
     RECT  36.137 38.16 36.277 38.424 ;
     RECT  36.065 16.368 36.385 20.424 ;
     RECT  35.104 3.936 36.421 4.776 ;
     RECT  35.104 41.904 36.421 41.928 ;
     RECT  35.165 42.96 36.421 43.128 ;
     RECT  35.417 44.88 36.421 45 ;
     RECT  35.813 31.92 36.533 31.944 ;
     RECT  36.421 44.4 36.601 45 ;
     RECT  36.029 45.984 36.601 46.584 ;
     RECT  35.104 39.888 36.637 40.872 ;
     RECT  36.275 10.128 36.709 10.824 ;
     RECT  35.219 35.808 36.716 36.36 ;
     RECT  36.637 39.792 36.745 40.872 ;
     RECT  36.421 41.904 36.745 43.128 ;
     RECT  35.489 12.336 36.781 14.856 ;
     RECT  35.345 7.44 36.805 7.752 ;
     RECT  36.805 7.44 36.817 8.232 ;
     RECT  36.716 35.808 36.817 36.456 ;
     RECT  36.781 12.288 36.901 14.856 ;
     RECT  36.385 15.888 36.901 20.424 ;
     RECT  36.137 34.08 36.901 34.824 ;
     RECT  36.817 35.808 36.901 36.648 ;
     RECT  36.901 12.288 36.908 20.424 ;
     RECT  36.421 3.936 36.994 5.256 ;
     RECT  36.817 6.72 37.004 8.232 ;
     RECT  36.994 3.936 37.177 5.304 ;
     RECT  37.004 6.72 37.177 8.424 ;
     RECT  36.925 31.776 37.429 31.8 ;
     RECT  37.177 3.936 37.465 8.424 ;
     RECT  36.601 44.4 37.465 46.584 ;
     RECT  36.485 2.832 37.508 2.856 ;
     RECT  37.465 3.888 37.508 8.424 ;
     RECT  36.709 9.456 37.508 10.824 ;
     RECT  36.908 12.144 37.508 20.424 ;
     RECT  35.813 21.648 37.508 29.256 ;
     RECT  36.817 30.48 37.508 30.648 ;
     RECT  37.429 31.728 37.508 31.8 ;
     RECT  36.901 34.08 37.508 36.648 ;
     RECT  36.277 37.632 37.508 38.424 ;
     RECT  36.745 39.792 37.508 43.128 ;
     RECT  37.465 44.4 37.508 46.824 ;
     RECT  36.029 48.672 37.508 49.032 ;
     RECT  37.508 2.148 37.612 49.692 ;
     RECT  37.612 2.256 37.804 49.422 ;
     RECT  37.804 30.768 37.901 31.896 ;
     RECT  37.804 27.408 37.973 29.064 ;
     RECT  37.901 31.776 37.973 31.896 ;
     RECT  37.804 3.888 38.003 18.744 ;
     RECT  38.003 11.424 38.405 18.744 ;
     RECT  38.405 11.424 38.621 18.024 ;
     RECT  37.804 19.776 38.621 20.52 ;
     RECT  37.804 49.008 38.621 49.032 ;
     RECT  37.804 32.976 38.657 37.608 ;
     RECT  38.657 32.976 38.723 35.352 ;
     RECT  38.003 3.888 38.729 10.392 ;
     RECT  38.621 20.256 38.729 20.52 ;
     RECT  37.804 22.224 38.729 26.328 ;
     RECT  38.729 4.272 38.765 10.392 ;
     RECT  37.804 38.592 38.873 38.808 ;
     RECT  38.657 36.528 38.909 37.608 ;
     RECT  38.621 11.424 38.915 17.688 ;
     RECT  38.909 36.528 38.981 37.512 ;
     RECT  38.915 11.424 39.053 16.008 ;
     RECT  37.804 42 39.301 43.128 ;
     RECT  37.804 44.112 39.301 47.88 ;
     RECT  37.901 30.768 39.337 30.792 ;
     RECT  39.301 42 39.337 47.88 ;
     RECT  37.804 2.256 39.356 2.28 ;
     RECT  38.729 22.32 39.661 26.328 ;
     RECT  39.337 41.952 39.733 47.88 ;
     RECT  37.973 31.872 39.769 31.896 ;
     RECT  38.723 32.976 39.769 35.064 ;
     RECT  39.733 41.952 39.769 48.408 ;
     RECT  39.661 22.32 39.841 26.808 ;
     RECT  39.356 2.256 39.877 3.24 ;
     RECT  39.769 41.952 39.925 48.984 ;
     RECT  39.841 22.32 40.069 26.904 ;
     RECT  37.973 28.512 40.069 29.064 ;
     RECT  38.915 17.136 40.201 17.688 ;
     RECT  39.877 2.256 40.208 3.336 ;
     RECT  38.765 4.512 40.208 10.392 ;
     RECT  39.053 11.424 40.208 15 ;
     RECT  39.053 15.984 40.208 16.008 ;
     RECT  40.201 17.136 40.208 18.168 ;
     RECT  38.729 20.256 40.208 20.328 ;
     RECT  40.069 22.32 40.208 29.064 ;
     RECT  39.337 30.576 40.208 30.792 ;
     RECT  39.769 31.872 40.208 35.064 ;
     RECT  38.981 36.528 40.208 36.648 ;
     RECT  37.804 39.792 40.208 40.584 ;
     RECT  39.925 41.856 40.208 48.984 ;
     RECT  40.208 2.148 40.312 49.692 ;
     RECT  40.312 2.256 40.504 49.422 ;
     RECT  40.504 30.576 40.673 30.6 ;
     RECT  40.504 43.104 40.691 43.128 ;
     RECT  40.504 39.792 40.709 41.976 ;
     RECT  40.504 5.04 40.781 10.392 ;
     RECT  40.781 6.624 40.889 10.392 ;
     RECT  40.504 37.056 40.889 37.08 ;
     RECT  40.889 6.624 40.925 8.52 ;
     RECT  40.504 19.344 40.931 21.048 ;
     RECT  40.504 2.256 40.997 3.336 ;
     RECT  40.709 39.84 41.069 41.976 ;
     RECT  40.504 44.16 41.105 47.448 ;
     RECT  40.781 5.184 41.249 5.544 ;
     RECT  40.504 22.32 41.315 29.064 ;
     RECT  40.925 6.816 41.501 8.52 ;
     RECT  41.105 44.16 41.641 47.112 ;
     RECT  41.069 40.416 41.645 41.976 ;
     RECT  40.504 48.432 41.645 48.984 ;
     RECT  40.504 16.608 41.677 18.168 ;
     RECT  40.931 19.344 41.677 19.416 ;
     RECT  40.504 31.776 41.708 32.28 ;
     RECT  40.504 33.888 41.708 35.352 ;
     RECT  41.708 31.248 41.749 32.28 ;
     RECT  41.708 33.888 41.749 35.928 ;
     RECT  41.315 24.096 41.785 29.064 ;
     RECT  41.249 5.184 41.789 5.256 ;
     RECT  41.749 31.248 41.795 35.928 ;
     RECT  40.997 2.592 41.845 3.336 ;
     RECT  41.845 2.592 41.891 4.104 ;
     RECT  40.504 11.952 41.893 14.76 ;
     RECT  41.891 2.592 41.933 2.904 ;
     RECT  40.889 9.888 41.933 10.392 ;
     RECT  41.891 4.08 42.109 4.104 ;
     RECT  41.789 5.184 42.109 5.208 ;
     RECT  41.501 6.816 42.109 6.888 ;
     RECT  41.645 41.424 42.145 41.976 ;
     RECT  41.641 43.536 42.145 47.112 ;
     RECT  42.037 37.056 42.181 37.08 ;
     RECT  41.785 24.096 42.253 29.544 ;
     RECT  41.677 16.608 42.332 19.416 ;
     RECT  41.893 11.376 42.361 14.76 ;
     RECT  42.181 37.056 42.541 37.608 ;
     RECT  41.501 7.968 42.565 8.52 ;
     RECT  41.645 40.416 42.685 40.44 ;
     RECT  42.145 41.424 42.721 47.112 ;
     RECT  42.109 6.24 42.757 6.888 ;
     RECT  42.565 7.968 42.757 8.712 ;
     RECT  42.685 39.744 42.757 40.44 ;
     RECT  42.721 41.424 42.757 47.4 ;
     RECT  42.757 39.744 42.829 47.4 ;
     RECT  42.109 4.08 42.865 5.208 ;
     RECT  42.757 6.24 42.865 8.712 ;
     RECT  41.933 2.88 42.908 2.904 ;
     RECT  42.865 4.08 42.908 8.712 ;
     RECT  41.933 9.888 42.908 10.2 ;
     RECT  42.361 11.376 42.908 15.336 ;
     RECT  42.332 16.512 42.908 19.416 ;
     RECT  40.931 20.496 42.908 21.048 ;
     RECT  41.315 22.32 42.908 23.112 ;
     RECT  42.253 24.096 42.908 29.88 ;
     RECT  41.795 31.776 42.908 35.928 ;
     RECT  42.541 37.056 42.908 37.656 ;
     RECT  42.829 39.744 42.908 47.448 ;
     RECT  41.645 48.48 42.908 48.984 ;
     RECT  42.908 2.148 43.012 49.692 ;
     RECT  43.012 2.418 43.204 49.422 ;
     RECT  43.204 44.304 43.265 47.4 ;
     RECT  43.204 9.072 43.331 9.096 ;
     RECT  43.204 31.392 43.331 37.992 ;
     RECT  43.204 5.232 43.337 7.752 ;
     RECT  43.204 10.08 43.379 18.216 ;
     RECT  43.204 48.768 43.625 48.984 ;
     RECT  43.204 21.648 43.811 27.048 ;
     RECT  43.337 5.232 43.949 7.512 ;
     RECT  43.204 2.736 43.955 3.96 ;
     RECT  43.204 39.216 43.985 42.744 ;
     RECT  43.379 10.08 44.003 15.192 ;
     RECT  43.985 39.312 44.021 42.744 ;
     RECT  43.379 16.416 44.057 18.216 ;
     RECT  43.811 21.648 44.099 26.568 ;
     RECT  44.057 18.192 44.129 18.216 ;
     RECT  43.955 2.736 44.237 3.192 ;
     RECT  44.237 2.736 44.269 2.904 ;
     RECT  44.003 10.08 44.269 14.76 ;
     RECT  43.204 19.248 44.269 20.04 ;
     RECT  43.949 6.864 44.305 7.512 ;
     RECT  43.331 31.68 44.389 37.992 ;
     RECT  44.021 39.888 44.414 42.744 ;
     RECT  44.269 19.248 44.437 20.28 ;
     RECT  43.949 5.232 44.453 5.688 ;
     RECT  44.269 9.12 44.485 14.76 ;
     RECT  43.265 44.304 44.521 47.352 ;
     RECT  44.437 19.248 44.524 20.856 ;
     RECT  44.389 31.68 44.525 38.136 ;
     RECT  44.524 19.248 44.593 20.136 ;
     RECT  43.625 48.768 44.593 48.792 ;
     RECT  44.414 39.888 44.597 42.696 ;
     RECT  44.453 5.664 44.605 5.688 ;
     RECT  43.204 28.224 44.629 30.408 ;
     RECT  44.521 44.208 44.725 47.352 ;
     RECT  44.629 27.888 44.773 30.408 ;
     RECT  44.773 27.888 44.809 30.456 ;
     RECT  44.525 31.68 44.809 31.704 ;
     RECT  44.057 16.416 44.953 16.824 ;
     RECT  44.525 32.88 44.953 38.136 ;
     RECT  44.099 22.272 45.025 26.568 ;
     RECT  44.809 27.888 45.025 31.704 ;
     RECT  44.305 6.864 45.097 7.704 ;
     RECT  44.485 8.832 45.097 14.76 ;
     RECT  44.953 15.84 45.169 16.824 ;
     RECT  44.269 2.256 45.277 2.904 ;
     RECT  44.953 32.88 45.568 38.712 ;
     RECT  45.169 15.84 45.601 17.64 ;
     RECT  45.277 2.256 45.608 3.432 ;
     RECT  44.809 4.56 45.608 4.584 ;
     RECT  45.097 6.864 45.608 14.76 ;
     RECT  45.601 15.84 45.608 17.928 ;
     RECT  44.593 19.2 45.608 20.136 ;
     RECT  45.241 21.168 45.608 21.192 ;
     RECT  45.025 22.272 45.608 31.704 ;
     RECT  45.568 32.88 45.608 38.76 ;
     RECT  44.597 39.888 45.608 40.392 ;
     RECT  44.597 41.376 45.608 42.696 ;
     RECT  44.725 44.208 45.608 47.736 ;
     RECT  44.593 48.768 45.608 49.032 ;
     RECT  45.608 2.148 45.712 49.692 ;
     RECT  45.712 2.256 45.857 49.422 ;
     RECT  45.857 2.418 45.904 49.422 ;
     RECT  45.904 2.784 45.965 3.432 ;
     RECT  45.904 12.336 46.019 26.904 ;
     RECT  45.904 39.84 46.045 44.952 ;
     RECT  45.904 31.68 46.067 33.288 ;
     RECT  45.904 34.896 46.08 34.92 ;
     RECT  45.904 37.968 46.109 37.992 ;
     RECT  46.045 41.376 46.153 44.952 ;
     RECT  45.904 6.864 46.433 10.728 ;
     RECT  46.019 16.8 46.505 19.656 ;
     RECT  46.019 21.168 46.505 26.904 ;
     RECT  46.505 21.168 46.685 26.664 ;
     RECT  46.505 17.04 46.721 19.656 ;
     RECT  46.433 7.392 46.757 10.728 ;
     RECT  46.067 31.872 46.793 32.28 ;
     RECT  46.045 39.84 46.793 40.392 ;
     RECT  46.153 44.352 46.793 44.952 ;
     RECT  46.019 12.336 46.829 15.336 ;
     RECT  46.721 19.248 46.865 19.656 ;
     RECT  45.904 45.984 46.969 47.832 ;
     RECT  45.904 49.008 46.969 49.032 ;
     RECT  46.829 12.336 46.973 15.288 ;
     RECT  45.904 36.384 47.045 36.6 ;
     RECT  46.969 45.984 47.081 49.032 ;
     RECT  46.721 17.04 47.153 18.024 ;
     RECT  46.153 41.376 47.153 43.32 ;
     RECT  46.973 12.336 47.257 12.888 ;
     RECT  47.045 36.384 47.293 36.408 ;
     RECT  45.965 3.408 47.324 3.432 ;
     RECT  47.324 3.36 47.329 3.432 ;
     RECT  46.865 19.344 47.329 19.656 ;
     RECT  47.329 3.36 47.365 3.96 ;
     RECT  45.904 5.088 47.365 5.208 ;
     RECT  45.904 28.224 47.401 30.456 ;
     RECT  47.329 38.208 47.401 38.232 ;
     RECT  47.293 35.52 47.413 36.408 ;
     RECT  46.067 33.264 47.42 33.288 ;
     RECT  47.413 35.28 47.461 36.408 ;
     RECT  47.401 38.112 47.473 38.232 ;
     RECT  46.685 21.696 47.509 26.664 ;
     RECT  47.401 27.696 47.509 30.456 ;
     RECT  46.793 44.4 47.545 44.952 ;
     RECT  47.081 45.984 47.545 48.456 ;
     RECT  47.365 3.36 47.617 5.208 ;
     RECT  46.757 7.68 47.725 10.728 ;
     RECT  47.545 44.4 47.761 48.456 ;
     RECT  47.725 7.68 47.797 10.92 ;
     RECT  46.793 39.84 48.013 39.864 ;
     RECT  47.617 3.36 48.308 6.12 ;
     RECT  47.797 7.632 48.308 10.92 ;
     RECT  47.257 11.952 48.308 12.888 ;
     RECT  46.973 14.112 48.308 15.288 ;
     RECT  47.153 17.04 48.308 17.064 ;
     RECT  47.329 19.344 48.308 20.472 ;
     RECT  47.509 21.696 48.308 30.456 ;
     RECT  47.257 31.728 48.308 31.752 ;
     RECT  47.42 33.264 48.308 33.72 ;
     RECT  47.461 34.752 48.308 36.408 ;
     RECT  47.473 38.016 48.308 38.232 ;
     RECT  48.013 39.36 48.308 39.864 ;
     RECT  47.153 41.376 48.308 42.744 ;
     RECT  47.761 43.824 48.308 48.456 ;
     RECT  48.308 2.148 48.412 49.692 ;
     RECT  48.412 2.418 48.604 49.422 ;
     RECT  48.604 44.4 48.629 44.952 ;
     RECT  48.604 5.52 48.665 6.12 ;
     RECT  48.604 10.128 48.665 10.92 ;
     RECT  48.604 22.32 48.701 29.064 ;
     RECT  48.665 5.52 48.737 5.544 ;
     RECT  48.701 22.32 48.755 26.616 ;
     RECT  48.604 7.632 48.845 7.656 ;
     RECT  48.604 34.704 49.061 34.728 ;
     RECT  48.604 12.336 49.349 15.912 ;
     RECT  48.604 46.032 50.065 46.632 ;
     RECT  48.629 44.928 50.137 44.952 ;
     RECT  50.065 45.936 50.137 46.632 ;
     RECT  49.349 14.112 50.425 15.912 ;
     RECT  49.349 12.336 50.713 12.888 ;
     RECT  50.425 14.112 50.713 16.008 ;
     RECT  48.755 22.32 50.713 23.112 ;
     RECT  48.755 24.24 50.713 26.616 ;
     RECT  48.701 27.6 50.713 29.064 ;
     RECT  50.137 44.928 50.713 46.632 ;
     RECT  48.665 10.128 51.221 10.152 ;
     RECT  50.713 22.32 51.509 29.064 ;
     RECT  51.509 22.56 51.545 29.064 ;
     RECT  51.545 22.752 51.581 29.064 ;
     RECT  50.713 12.336 51.653 16.008 ;
     RECT  50.713 44.928 51.688 46.728 ;
     RECT  51.653 12.528 51.761 16.008 ;
     RECT  51.761 13.008 51.804 16.008 ;
     RECT  51.581 22.992 51.804 29.064 ;
     RECT  51.688 44.88 51.804 46.728 ;
    LAYER M5 ;
     RECT  2.4 2.137 2.52 2.151 ;
     RECT  5.1 2.137 5.22 2.151 ;
     RECT  7.8 2.137 7.92 2.151 ;
     RECT  10.5 2.137 10.62 2.151 ;
     RECT  13.2 2.137 13.32 2.151 ;
     RECT  15.9 2.137 16.02 2.151 ;
     RECT  18.6 2.137 18.72 2.151 ;
     RECT  21.3 2.137 21.42 2.151 ;
     RECT  24 2.137 24.12 2.151 ;
     RECT  26.7 2.137 26.82 2.151 ;
     RECT  29.4 2.137 29.52 2.151 ;
     RECT  32.1 2.137 32.22 2.151 ;
     RECT  34.8 2.137 34.92 2.151 ;
     RECT  37.5 2.137 37.62 2.151 ;
     RECT  40.2 2.137 40.32 2.151 ;
     RECT  42.9 2.137 43.02 2.151 ;
     RECT  45.6 2.137 45.72 2.151 ;
     RECT  48.3 2.137 48.42 2.151 ;
     RECT  7.8 2.151 8.112 2.245 ;
     RECT  13.2 2.151 13.512 2.245 ;
     RECT  29.4 2.151 29.712 2.245 ;
     RECT  40.2 2.151 40.512 2.245 ;
     RECT  15.9 2.151 16.212 2.581 ;
     RECT  26.7 2.151 27.012 2.629 ;
     RECT  37.5 2.151 37.812 2.821 ;
     RECT  10.5 2.151 10.812 2.869 ;
     RECT  29.4 2.245 30.264 2.915 ;
     RECT  42.9 2.151 43.212 3.157 ;
     RECT  39.744 2.245 40.512 3.205 ;
     RECT  7.8 2.245 8.232 3.349 ;
     RECT  48.3 2.151 48.612 3.349 ;
     RECT  15.648 2.581 17.064 3.539 ;
     RECT  7.8 3.349 8.904 3.925 ;
     RECT  34.8 2.151 35.112 3.925 ;
     RECT  36.528 2.821 37.812 3.925 ;
     RECT  36.528 3.925 37.944 3.971 ;
     RECT  41.856 2.821 41.88 4.115 ;
     RECT  47.376 3.349 48.612 4.163 ;
     RECT  5.1 2.151 5.412 4.405 ;
     RECT  18.6 2.151 18.912 4.501 ;
     RECT  19.968 3.397 19.992 4.501 ;
     RECT  18.6 4.501 19.992 4.643 ;
     RECT  34.8 3.925 35.256 4.643 ;
     RECT  26.7 2.629 27.576 4.645 ;
     RECT  32.1 2.151 32.412 4.645 ;
     RECT  7.68 3.925 8.904 4.691 ;
     RECT  15.648 3.539 16.212 4.837 ;
     RECT  31.296 4.645 32.412 5.027 ;
     RECT  5.1 4.405 5.688 5.029 ;
     RECT  2.4 2.151 2.712 5.077 ;
     RECT  42.9 3.157 43.944 5.267 ;
     RECT  21.3 2.151 21.612 5.701 ;
     RECT  5.1 5.029 6.456 5.845 ;
     RECT  7.8 4.691 8.904 5.845 ;
     RECT  4.896 5.845 8.904 5.891 ;
     RECT  24 2.151 24.312 6.133 ;
     RECT  4.896 5.891 8.112 6.179 ;
     RECT  21.168 5.701 21.612 6.805 ;
     RECT  4.896 6.179 5.688 6.851 ;
     RECT  44.544 5.653 44.568 6.899 ;
     RECT  23.568 6.133 24.312 6.947 ;
     RECT  2.4 5.077 2.808 7.043 ;
     RECT  32.1 5.027 32.412 7.141 ;
     RECT  15.408 4.837 16.212 7.237 ;
     RECT  7.296 6.179 8.112 7.381 ;
     RECT  29.4 2.915 29.712 7.381 ;
     RECT  45.6 2.151 45.912 7.381 ;
     RECT  32.1 7.141 33.048 7.621 ;
     RECT  21.168 6.805 22.248 7.667 ;
     RECT  36.96 3.971 37.944 7.717 ;
     RECT  36.24 7.717 37.944 7.909 ;
     RECT  42.9 5.267 43.212 7.957 ;
     RECT  9.984 2.869 10.812 8.003 ;
     RECT  31.968 7.621 33.048 8.003 ;
     RECT  6.864 7.381 8.112 8.435 ;
     RECT  24 6.947 24.312 8.437 ;
     RECT  15.216 7.237 16.212 8.485 ;
     RECT  15.216 8.485 16.344 8.531 ;
     RECT  36.24 7.909 37.992 8.531 ;
     RECT  5.1 6.851 5.688 8.579 ;
     RECT  39.408 3.205 40.512 8.675 ;
     RECT  44.976 7.381 45.912 8.725 ;
     RECT  23.712 8.437 24.312 8.773 ;
     RECT  44.976 8.725 46.776 8.867 ;
     RECT  26.7 4.645 27.72 8.965 ;
     RECT  3.936 7.957 3.96 9.011 ;
     RECT  12.384 2.245 13.512 9.061 ;
     RECT  42.576 7.957 43.212 9.061 ;
     RECT  31.968 8.003 32.412 9.155 ;
     RECT  23.712 8.773 24.408 9.251 ;
     RECT  15.408 8.531 16.344 9.493 ;
     RECT  29.28 7.381 29.712 9.539 ;
     RECT  15.408 9.493 16.536 9.589 ;
     RECT  5.1 8.579 5.544 9.637 ;
     RECT  7.296 8.435 8.112 9.637 ;
     RECT  45.6 8.867 46.776 9.731 ;
     RECT  12.384 9.061 13.704 9.779 ;
     RECT  10.5 8.003 10.812 9.781 ;
     RECT  2.4 7.043 2.712 9.925 ;
     RECT  13.2 9.779 13.704 10.115 ;
     RECT  48.192 4.163 48.612 10.165 ;
     RECT  42.576 9.061 43.32 10.211 ;
     RECT  32.1 9.155 32.412 10.261 ;
     RECT  29.4 9.539 29.712 10.501 ;
     RECT  42.672 10.211 43.32 10.595 ;
     RECT  36.24 8.531 37.812 10.597 ;
     RECT  47.856 10.165 48.612 10.739 ;
     RECT  2.4 9.925 3.432 10.787 ;
     RECT  48.192 10.739 48.612 10.883 ;
     RECT  24 9.251 24.408 10.885 ;
     RECT  26.592 8.965 27.72 11.077 ;
     RECT  21.3 7.667 22.248 11.219 ;
     RECT  36.24 10.597 37.992 11.507 ;
     RECT  29.4 10.501 30.024 11.509 ;
     RECT  45.6 9.731 45.912 11.509 ;
     RECT  18.6 4.643 19.368 11.653 ;
     RECT  18.192 11.653 19.368 11.699 ;
     RECT  10.368 9.781 10.812 11.941 ;
     RECT  42.672 10.595 43.212 11.941 ;
     RECT  26.592 11.077 27.816 12.179 ;
     RECT  31.344 10.261 32.412 12.515 ;
     RECT  9.792 11.941 10.812 12.517 ;
     RECT  9.792 12.517 11.4 12.563 ;
     RECT  24 10.885 24.888 12.565 ;
     RECT  3.84 11.365 3.864 12.611 ;
     RECT  29.4 11.509 30.312 12.709 ;
     RECT  44.832 11.509 45.912 12.755 ;
     RECT  22.8 12.661 22.824 12.803 ;
     RECT  23.904 12.565 24.888 12.947 ;
     RECT  29.184 12.709 30.312 13.043 ;
     RECT  39.648 8.675 40.512 13.091 ;
     RECT  24 12.947 24.888 13.331 ;
     RECT  29.4 13.043 30.312 13.571 ;
     RECT  36.24 11.507 37.812 13.621 ;
     RECT  42.624 11.941 43.212 13.621 ;
     RECT  32.1 12.515 32.412 13.669 ;
     RECT  18.192 11.699 18.912 13.715 ;
     RECT  42.624 13.621 43.992 13.715 ;
     RECT  15.408 9.589 17.064 13.813 ;
     RECT  13.2 10.115 13.512 14.197 ;
     RECT  26.7 12.179 27.816 14.197 ;
     RECT  34.8 4.643 35.112 14.197 ;
     RECT  36.24 13.621 37.944 14.197 ;
     RECT  5.1 9.637 8.112 14.243 ;
     RECT  32.1 13.669 32.952 14.387 ;
     RECT  29.4 13.571 29.712 14.869 ;
     RECT  26.208 14.197 27.816 14.963 ;
     RECT  22.704 14.917 22.728 14.965 ;
     RECT  26.208 14.963 27.012 15.061 ;
     RECT  42.9 13.715 43.992 15.203 ;
     RECT  5.1 14.243 6.072 15.253 ;
     RECT  45.6 12.755 45.912 15.301 ;
     RECT  22.704 14.965 22.824 15.347 ;
     RECT  10.272 12.563 11.4 15.395 ;
     RECT  34.8 14.197 37.944 15.491 ;
     RECT  2.4 10.787 2.712 15.541 ;
     RECT  22.704 15.347 22.728 15.683 ;
     RECT  2.304 15.541 2.712 15.731 ;
     RECT  7.392 14.243 8.112 15.731 ;
     RECT  13.2 14.197 13.992 15.827 ;
     RECT  15.408 13.813 17.4 15.973 ;
     RECT  18.6 13.715 18.912 15.973 ;
     RECT  4.464 15.253 6.072 16.019 ;
     RECT  24 13.331 24.408 16.019 ;
     RECT  31.056 14.773 31.08 16.019 ;
     RECT  42.9 15.203 43.368 16.019 ;
     RECT  29.04 14.869 29.712 16.307 ;
     RECT  42.9 16.019 43.212 16.501 ;
     RECT  40.2 13.091 40.512 16.789 ;
     RECT  42.384 16.501 43.212 16.835 ;
     RECT  15.408 15.973 18.912 16.931 ;
     RECT  24 16.019 24.312 16.933 ;
     RECT  5.1 16.019 6.072 17.077 ;
     RECT  7.8 15.731 8.112 17.077 ;
     RECT  13.2 15.827 13.512 17.077 ;
     RECT  34.8 15.491 37.812 17.077 ;
     RECT  15.792 16.931 18.912 17.123 ;
     RECT  38.88 16.501 38.904 17.171 ;
     RECT  32.1 14.387 32.412 17.365 ;
     RECT  32.1 17.365 33.144 17.413 ;
     RECT  34.224 17.077 37.812 17.413 ;
     RECT  10.272 15.395 10.812 17.509 ;
     RECT  45.6 15.301 46.008 17.509 ;
     RECT  5.1 17.077 8.112 17.605 ;
     RECT  18.6 17.123 18.912 17.605 ;
     RECT  21.3 11.219 21.612 17.605 ;
     RECT  42.9 16.835 43.212 17.605 ;
     RECT  32.1 17.413 38.232 17.651 ;
     RECT  32.1 17.651 35.112 17.795 ;
     RECT  13.104 17.077 13.512 17.843 ;
     RECT  29.4 16.307 29.712 17.941 ;
     RECT  30.72 16.501 30.744 17.941 ;
     RECT  29.4 17.941 30.744 17.987 ;
     RECT  42.9 17.605 43.368 18.181 ;
     RECT  42.192 18.181 43.368 18.227 ;
     RECT  23.76 16.933 24.312 18.275 ;
     RECT  18.6 17.605 19.176 18.373 ;
     RECT  4.704 17.605 8.112 18.419 ;
     RECT  33.408 17.795 35.112 18.419 ;
     RECT  29.4 17.987 30.168 18.563 ;
     RECT  20.592 17.605 21.612 18.613 ;
     RECT  20.592 18.613 21.72 18.659 ;
     RECT  13.2 17.843 13.512 18.709 ;
     RECT  32.1 17.795 32.412 18.709 ;
     RECT  15.792 17.123 17.208 18.757 ;
     RECT  26.016 15.061 27.012 18.757 ;
     RECT  26.016 18.757 27.72 18.803 ;
     RECT  24 18.275 24.312 18.805 ;
     RECT  34.8 18.419 35.112 18.805 ;
     RECT  5.1 18.419 8.112 18.851 ;
     RECT  15.264 18.757 17.208 19.141 ;
     RECT  31.968 18.709 32.412 19.235 ;
     RECT  24 18.805 25.128 19.379 ;
     RECT  13.2 18.709 13.608 19.427 ;
     RECT  42.192 18.227 43.212 19.427 ;
     RECT  7.488 18.851 8.112 19.571 ;
     RECT  10.224 17.509 10.812 19.573 ;
     RECT  26.7 18.803 27.72 19.621 ;
     RECT  45.6 17.509 46.344 19.667 ;
     RECT  36.24 17.651 38.232 19.811 ;
     RECT  18.6 18.373 19.512 20.003 ;
     RECT  36.24 19.811 37.812 20.003 ;
     RECT  0.144 20.101 0.168 20.387 ;
     RECT  18.6 20.003 19.032 20.387 ;
     RECT  32.1 19.235 32.412 20.389 ;
     RECT  33.408 18.419 33.432 20.389 ;
     RECT  5.1 18.851 5.928 20.437 ;
     RECT  48.3 10.883 48.612 20.437 ;
     RECT  21.024 18.659 21.72 20.579 ;
     RECT  34.8 18.805 35.256 20.579 ;
     RECT  26.7 19.621 27.816 20.723 ;
     RECT  15.264 19.141 17.352 20.867 ;
     RECT  44.448 19.285 44.472 20.867 ;
     RECT  13.2 19.427 13.512 20.869 ;
     RECT  29.4 18.563 29.712 20.869 ;
     RECT  4.368 20.437 5.928 21.107 ;
     RECT  5.1 21.107 5.928 21.155 ;
     RECT  9.12 18.517 9.144 21.395 ;
     RECT  21.024 20.579 21.612 21.443 ;
     RECT  7.8 19.571 8.112 21.541 ;
     RECT  42.9 19.427 43.212 21.637 ;
     RECT  28.752 20.869 29.712 21.731 ;
     RECT  18.6 20.387 18.912 21.925 ;
     RECT  10.224 19.573 11.64 22.163 ;
     RECT  31.056 20.965 31.08 22.211 ;
     RECT  37.152 20.003 37.812 22.213 ;
     RECT  45.6 19.667 46.008 22.259 ;
     RECT  10.224 22.163 10.92 22.739 ;
     RECT  26.7 20.723 27.72 22.741 ;
     RECT  34.8 20.579 35.112 22.741 ;
     RECT  42.9 21.637 44.088 22.787 ;
     RECT  40.2 16.789 40.92 22.789 ;
     RECT  37.152 22.213 37.944 22.883 ;
     RECT  29.4 21.731 29.712 23.173 ;
     RECT  39.648 22.789 40.92 23.269 ;
     RECT  26.064 22.741 27.72 23.363 ;
     RECT  7.8 21.541 8.232 23.459 ;
     RECT  47.472 20.437 48.612 23.605 ;
     RECT  13.2 20.869 13.656 23.845 ;
     RECT  10.272 22.739 10.92 23.941 ;
     RECT  26.7 23.363 27.72 23.941 ;
     RECT  47.472 23.605 48.744 24.037 ;
     RECT  47.136 24.037 48.744 24.083 ;
     RECT  15.9 20.867 17.352 24.131 ;
     RECT  34.8 22.741 35.736 24.131 ;
     RECT  0.144 24.085 0.168 24.467 ;
     RECT  22.944 23.701 22.968 24.515 ;
     RECT  30.816 23.317 30.84 24.659 ;
     RECT  32.1 20.389 33.432 24.659 ;
     RECT  39.648 23.269 41.304 24.659 ;
     RECT  47.136 24.083 47.16 24.899 ;
     RECT  39.648 24.659 40.512 24.949 ;
     RECT  15.9 24.131 17.064 25.045 ;
     RECT  0.192 24.709 0.216 25.091 ;
     RECT  32.1 24.659 33.336 25.139 ;
     RECT  39.36 24.949 40.512 25.139 ;
     RECT  18.6 21.925 19.032 25.283 ;
     RECT  29.088 23.173 29.712 25.429 ;
     RECT  13.104 23.845 13.656 25.475 ;
     RECT  26.7 23.941 27.912 25.715 ;
     RECT  29.088 25.429 29.832 25.717 ;
     RECT  15.456 25.045 17.064 25.765 ;
     RECT  29.088 25.717 30.264 25.765 ;
     RECT  15.36 25.765 17.064 25.811 ;
     RECT  10.272 23.941 11.256 25.909 ;
     RECT  37.152 22.883 37.812 25.955 ;
     RECT  9.984 25.909 11.256 26.005 ;
     RECT  48.3 24.083 48.744 26.005 ;
     RECT  29.088 25.765 30.888 26.051 ;
     RECT  51.648 25.765 51.672 26.051 ;
     RECT  47.76 26.005 48.744 26.195 ;
     RECT  34.8 24.131 35.208 26.245 ;
     RECT  42.9 22.787 43.212 26.245 ;
     RECT  45.6 22.259 45.912 26.245 ;
     RECT  5.1 21.155 5.88 26.291 ;
     RECT  15.36 25.811 16.344 26.291 ;
     RECT  45.024 26.245 45.912 26.435 ;
     RECT  5.1 26.291 5.412 26.629 ;
     RECT  13.2 25.475 13.656 26.629 ;
     RECT  9.984 26.005 11.544 26.725 ;
     RECT  18.6 25.283 18.912 26.725 ;
     RECT  13.056 26.629 13.656 26.771 ;
     RECT  40.2 25.139 40.512 26.773 ;
     RECT  29.088 26.051 30.264 26.819 ;
     RECT  7.8 23.459 8.112 26.965 ;
     RECT  42.9 26.245 43.8 27.059 ;
     RECT  9.792 26.725 11.544 27.157 ;
     RECT  29.088 26.819 29.712 27.203 ;
     RECT  18.6 26.725 19.32 27.635 ;
     RECT  34.8 26.245 35.256 27.731 ;
     RECT  15.36 26.291 16.212 27.733 ;
     RECT  37.344 25.955 37.812 27.733 ;
     RECT  15.216 27.733 16.212 27.877 ;
     RECT  24 19.379 24.312 27.877 ;
     RECT  25.536 27.205 25.56 27.971 ;
     RECT  48.3 26.195 48.744 27.971 ;
     RECT  7.344 26.965 8.112 28.211 ;
     RECT  45.504 26.435 45.912 28.211 ;
     RECT  42.9 27.059 43.212 28.261 ;
     RECT  4.512 26.629 5.412 28.741 ;
     RECT  24 27.877 24.408 28.835 ;
     RECT  40.08 26.773 40.512 28.837 ;
     RECT  13.2 26.771 13.656 29.029 ;
     RECT  36.624 27.733 37.812 29.267 ;
     RECT  9.792 27.157 11.688 29.365 ;
     RECT  13.104 29.029 13.656 29.365 ;
     RECT  4.08 28.741 5.412 29.459 ;
     RECT  7.8 28.211 8.112 29.605 ;
     RECT  9.792 29.365 13.656 29.605 ;
     RECT  18.6 27.635 18.912 29.605 ;
     RECT  45.6 28.211 45.912 29.605 ;
     RECT  26.7 25.715 27.012 30.133 ;
     RECT  7.8 29.605 13.656 30.179 ;
     RECT  30.816 28.453 30.84 30.229 ;
     RECT  32.1 25.139 32.664 30.229 ;
     RECT  30.816 30.229 32.664 30.275 ;
     RECT  15.216 27.877 16.344 30.371 ;
     RECT  7.8 30.179 11.688 30.419 ;
     RECT  31.584 30.275 32.664 30.467 ;
     RECT  15.36 30.371 16.344 30.757 ;
     RECT  18.6 29.605 19.272 30.851 ;
     RECT  9.792 30.419 11.688 31.139 ;
     RECT  10.224 31.139 11.688 31.237 ;
     RECT  5.1 29.459 5.412 31.285 ;
     RECT  24 28.835 24.312 31.285 ;
     RECT  26.7 30.133 27.528 31.427 ;
     RECT  42.9 28.261 43.32 31.427 ;
     RECT  45.6 29.605 46.008 31.669 ;
     RECT  15.36 30.757 16.392 31.811 ;
     RECT  23.424 31.285 24.312 32.197 ;
     RECT  23.424 32.197 25.08 32.243 ;
     RECT  7.8 30.419 8.112 32.293 ;
     RECT  31.584 30.467 32.412 32.341 ;
     RECT  33.792 31.237 33.816 32.341 ;
     RECT  31.584 32.341 33.816 32.387 ;
     RECT  34.8 27.731 35.112 32.437 ;
     RECT  44.352 31.669 44.376 32.483 ;
     RECT  4.08 29.459 4.104 33.107 ;
     RECT  31.584 32.387 33.096 33.107 ;
     RECT  7.392 32.293 8.112 33.109 ;
     RECT  41.76 31.237 41.784 33.155 ;
     RECT  45.6 31.669 46.056 33.299 ;
     RECT  15.36 31.811 16.212 33.541 ;
     RECT  18.6 30.851 18.912 33.541 ;
     RECT  5.1 31.285 6.312 33.589 ;
     RECT  26.7 31.427 27.012 33.589 ;
     RECT  7.392 33.109 8.232 33.683 ;
     RECT  48.3 27.971 48.612 33.685 ;
     RECT  10.224 31.237 11.976 33.779 ;
     RECT  4.992 33.589 6.312 33.827 ;
     RECT  10.272 33.779 11.976 33.877 ;
     RECT  39.744 28.837 40.512 33.925 ;
     RECT  36.864 29.267 37.812 33.973 ;
     RECT  4.992 33.827 5.412 34.355 ;
     RECT  31.584 33.107 32.412 34.357 ;
     RECT  39.744 33.925 40.632 34.739 ;
     RECT  29.4 27.203 29.712 34.741 ;
     RECT  42.9 31.427 43.212 34.789 ;
     RECT  3.936 34.165 3.96 34.835 ;
     RECT  36.864 33.973 38.712 34.885 ;
     RECT  39.744 34.739 40.512 34.885 ;
     RECT  42 34.789 43.212 34.885 ;
     RECT  24 32.243 25.08 34.931 ;
     RECT  45.6 33.299 46.008 34.931 ;
     RECT  26.112 33.589 27.012 34.979 ;
     RECT  34.8 32.437 35.208 34.979 ;
     RECT  36.864 34.885 40.512 35.027 ;
     RECT  39.744 35.027 40.512 35.075 ;
     RECT  24 34.931 24.312 35.269 ;
     RECT  47.472 33.685 48.612 35.269 ;
     RECT  10.272 33.877 12.216 35.317 ;
     RECT  13.2 30.179 13.656 35.317 ;
     RECT  15.36 33.541 17.112 35.363 ;
     RECT  29.4 34.741 30.264 35.363 ;
     RECT  36.864 35.027 38.712 35.363 ;
     RECT  23.136 35.269 24.312 35.411 ;
     RECT  31.584 34.357 33.048 35.699 ;
     RECT  7.392 33.683 8.112 35.843 ;
     RECT  41.76 34.885 43.212 35.939 ;
     RECT  2.4 15.731 2.712 35.989 ;
     RECT  18.48 33.541 18.912 36.131 ;
     RECT  47.424 35.269 48.612 36.419 ;
     RECT  26.7 34.979 27.012 36.421 ;
     RECT  28.176 31.669 28.2 36.421 ;
     RECT  36.864 35.363 37.812 36.421 ;
     RECT  7.8 35.843 8.112 36.901 ;
     RECT  15.36 35.363 16.536 37.091 ;
     RECT  26.7 36.421 28.2 37.093 ;
     RECT  2.4 35.989 3.432 37.283 ;
     RECT  34.8 34.979 35.112 37.429 ;
     RECT  15.36 37.091 16.212 37.573 ;
     RECT  21.12 21.443 21.612 37.667 ;
     RECT  10.272 35.317 13.656 38.003 ;
     RECT  32.1 35.699 33.048 38.101 ;
     RECT  44.4 37.045 44.424 38.147 ;
     RECT  32.1 38.101 33.144 38.149 ;
     RECT  34.464 37.429 35.112 38.149 ;
     RECT  25.632 37.861 25.656 38.197 ;
     RECT  26.7 37.093 28.248 38.197 ;
     RECT  48.3 36.419 48.612 38.197 ;
     RECT  25.632 38.197 28.248 38.243 ;
     RECT  14.784 37.573 16.212 38.675 ;
     RECT  32.1 38.149 35.112 38.771 ;
     RECT  7.8 36.901 8.568 38.773 ;
     RECT  2.4 37.283 2.904 39.109 ;
     RECT  25.632 38.243 27.012 39.205 ;
     RECT  18.6 36.131 18.912 39.301 ;
     RECT  48.096 38.197 48.612 39.395 ;
     RECT  28.224 38.243 28.248 39.539 ;
     RECT  5.1 34.355 5.412 39.589 ;
     RECT  7.8 38.773 8.856 39.589 ;
     RECT  15.36 38.675 16.212 39.733 ;
     RECT  25.632 39.205 27.144 39.779 ;
     RECT  7.8 39.589 9.096 39.781 ;
     RECT  10.368 38.003 13.656 39.781 ;
     RECT  18.24 39.301 18.912 39.827 ;
     RECT  45.6 34.931 45.912 39.829 ;
     RECT  34.8 38.771 35.112 39.877 ;
     RECT  36.768 36.421 37.812 39.877 ;
     RECT  2.4 39.109 3.048 39.923 ;
     RECT  7.8 39.781 13.656 40.019 ;
     RECT  14.928 39.733 16.212 40.117 ;
     RECT  40.2 35.075 40.512 40.405 ;
     RECT  40.2 40.405 40.68 40.549 ;
     RECT  21.3 37.667 21.612 40.693 ;
     RECT  42.9 35.939 43.212 40.741 ;
     RECT  32.1 38.771 33.144 40.837 ;
     RECT  29.4 35.363 29.712 40.933 ;
     RECT  32.1 40.837 33.624 40.933 ;
     RECT  14.928 40.117 16.344 41.171 ;
     RECT  31.872 40.933 33.624 41.171 ;
     RECT  45.6 39.829 46.776 41.411 ;
     RECT  7.8 40.019 8.112 41.413 ;
     RECT  31.872 41.171 32.412 41.747 ;
     RECT  44.448 41.653 44.472 41.987 ;
     RECT  6.816 41.413 8.112 41.989 ;
     RECT  6.768 41.989 8.112 42.037 ;
     RECT  9.648 40.019 13.656 42.037 ;
     RECT  6.768 42.037 13.656 42.083 ;
     RECT  21.168 40.693 21.612 42.179 ;
     RECT  18.6 39.827 18.912 42.181 ;
     RECT  39.936 40.549 40.68 42.373 ;
     RECT  22.752 39.877 22.776 42.565 ;
     RECT  24 35.411 24.312 42.565 ;
     RECT  10.272 42.083 13.656 42.707 ;
     RECT  32.1 41.747 32.412 42.709 ;
     RECT  29.232 40.933 29.712 42.755 ;
     RECT  42.768 40.741 43.212 42.803 ;
     RECT  34.8 39.877 37.812 42.995 ;
     RECT  18.192 42.181 18.912 43.043 ;
     RECT  36.768 42.995 37.812 43.139 ;
     RECT  39.36 42.373 40.68 43.139 ;
     RECT  21.3 42.179 21.612 43.141 ;
     RECT  22.752 42.565 24.312 43.141 ;
     RECT  33.6 41.171 33.624 43.237 ;
     RECT  39.36 43.139 40.512 43.237 ;
     RECT  14.928 41.171 16.212 43.523 ;
     RECT  26.7 39.779 27.144 43.571 ;
     RECT  18.6 43.043 18.912 43.573 ;
     RECT  6.768 42.083 8.904 43.763 ;
     RECT  29.28 42.755 29.712 43.763 ;
     RECT  15.792 43.523 16.212 43.813 ;
     RECT  4.32 39.589 5.412 43.861 ;
     RECT  6.768 43.763 6.792 43.861 ;
     RECT  45.6 41.411 46.056 43.861 ;
     RECT  21.3 43.141 24.312 43.955 ;
     RECT  7.8 43.763 8.904 44.051 ;
     RECT  33.552 43.237 33.624 44.053 ;
     RECT  31.296 42.709 32.412 44.099 ;
     RECT  45.6 43.861 46.104 44.197 ;
     RECT  15.792 43.813 16.344 44.293 ;
     RECT  37.5 43.139 37.812 44.437 ;
     RECT  4.32 43.861 6.792 44.483 ;
     RECT  22.848 43.955 24.312 44.483 ;
     RECT  25.632 39.779 25.656 44.483 ;
     RECT  33.504 44.053 33.624 44.627 ;
     RECT  15.792 44.293 16.392 44.917 ;
     RECT  15.792 44.917 16.44 44.963 ;
     RECT  13.056 42.707 13.656 44.965 ;
     RECT  18.6 43.573 19.272 44.965 ;
     RECT  26.7 43.571 27.012 44.965 ;
     RECT  2.4 39.923 2.712 45.541 ;
     RECT  4.32 44.483 6.408 45.541 ;
     RECT  32.1 44.099 32.412 45.541 ;
     RECT  39.312 43.237 40.512 45.541 ;
     RECT  36.624 44.437 37.812 45.635 ;
     RECT  45.024 44.197 46.104 45.635 ;
     RECT  18.6 44.965 19.608 46.115 ;
     RECT  2.4 45.541 6.408 46.211 ;
     RECT  18.6 46.115 19.272 46.211 ;
     RECT  45.6 45.635 46.104 46.261 ;
     RECT  45.6 46.261 47.016 46.741 ;
     RECT  48.3 39.395 48.612 46.741 ;
     RECT  31.44 45.541 32.412 46.787 ;
     RECT  45.6 46.741 48.612 46.883 ;
     RECT  39.216 45.541 40.512 46.931 ;
     RECT  12.96 44.965 13.656 47.027 ;
     RECT  45.6 46.883 47.016 47.123 ;
     RECT  42.9 42.803 43.212 47.173 ;
     RECT  5.1 46.211 6.408 47.269 ;
     RECT  14.688 45.541 14.712 47.269 ;
     RECT  15.9 44.963 16.44 47.269 ;
     RECT  2.4 46.211 3.432 47.315 ;
     RECT  12.96 47.027 13.512 47.555 ;
     RECT  33.552 44.627 33.624 47.701 ;
     RECT  34.8 42.995 35.112 47.701 ;
     RECT  45.6 47.123 45.912 47.701 ;
     RECT  46.992 47.123 47.016 47.843 ;
     RECT  39.312 46.931 40.512 47.891 ;
     RECT  14.688 47.269 16.44 47.939 ;
     RECT  33.552 47.701 35.112 47.987 ;
     RECT  10.272 42.707 11.688 48.515 ;
     RECT  26.7 44.965 27.96 48.515 ;
     RECT  39.888 47.891 40.512 48.707 ;
     RECT  42.768 47.173 43.212 48.803 ;
     RECT  44.736 47.701 45.912 48.803 ;
     RECT  15.264 47.939 16.44 48.805 ;
     RECT  21.3 43.955 21.612 48.901 ;
     RECT  4.896 47.269 6.408 48.947 ;
     RECT  15.264 48.805 17.208 48.947 ;
     RECT  15.264 48.947 17.112 49.043 ;
     RECT  21.072 48.901 21.612 49.043 ;
     RECT  23.616 44.483 24.312 49.043 ;
     RECT  6.384 48.947 6.408 49.091 ;
     RECT  4.896 48.947 5.412 49.187 ;
     RECT  15.9 49.043 17.112 49.235 ;
     RECT  33.888 47.987 35.112 49.475 ;
     RECT  2.4 47.315 2.712 49.689 ;
     RECT  5.1 49.187 5.412 49.689 ;
     RECT  7.8 44.051 8.112 49.689 ;
     RECT  13.2 47.555 13.512 49.689 ;
     RECT  15.9 49.235 16.212 49.689 ;
     RECT  18.6 46.211 18.912 49.689 ;
     RECT  21.3 49.043 21.612 49.689 ;
     RECT  24 49.043 24.312 49.689 ;
     RECT  26.7 48.515 27.012 49.689 ;
     RECT  29.4 43.763 29.712 49.689 ;
     RECT  32.1 46.787 32.412 49.689 ;
     RECT  34.8 49.475 35.112 49.689 ;
     RECT  37.5 45.635 37.812 49.689 ;
     RECT  40.2 48.707 40.512 49.689 ;
     RECT  42.9 48.803 43.212 49.689 ;
     RECT  45.6 48.803 45.912 49.689 ;
     RECT  48.3 46.883 48.612 49.689 ;
     RECT  2.4 49.689 2.52 49.703 ;
     RECT  5.1 49.689 5.22 49.703 ;
     RECT  7.8 49.689 7.92 49.703 ;
     RECT  10.5 48.515 11.688 49.703 ;
     RECT  13.2 49.689 13.32 49.703 ;
     RECT  15.9 49.689 16.02 49.703 ;
     RECT  18.6 49.689 18.72 49.703 ;
     RECT  21.3 49.689 21.42 49.703 ;
     RECT  24 49.689 24.12 49.703 ;
     RECT  26.7 49.689 26.82 49.703 ;
     RECT  29.4 49.689 29.52 49.703 ;
     RECT  32.1 49.689 32.22 49.703 ;
     RECT  34.8 49.689 34.92 49.703 ;
     RECT  37.5 49.689 37.62 49.703 ;
     RECT  40.2 49.689 40.32 49.703 ;
     RECT  42.9 49.689 43.02 49.703 ;
     RECT  45.6 49.689 45.72 49.703 ;
     RECT  48.3 49.689 48.42 49.703 ;
     RECT  11.52 49.703 11.688 51.635 ;
     RECT  11.664 51.635 11.688 51.779 ;
  END
END qfd_landh0d8gn_116_EW_52x52
END LIBRARY
